VERSION 5.7 ;
BUSBITCHARS "[]" ;
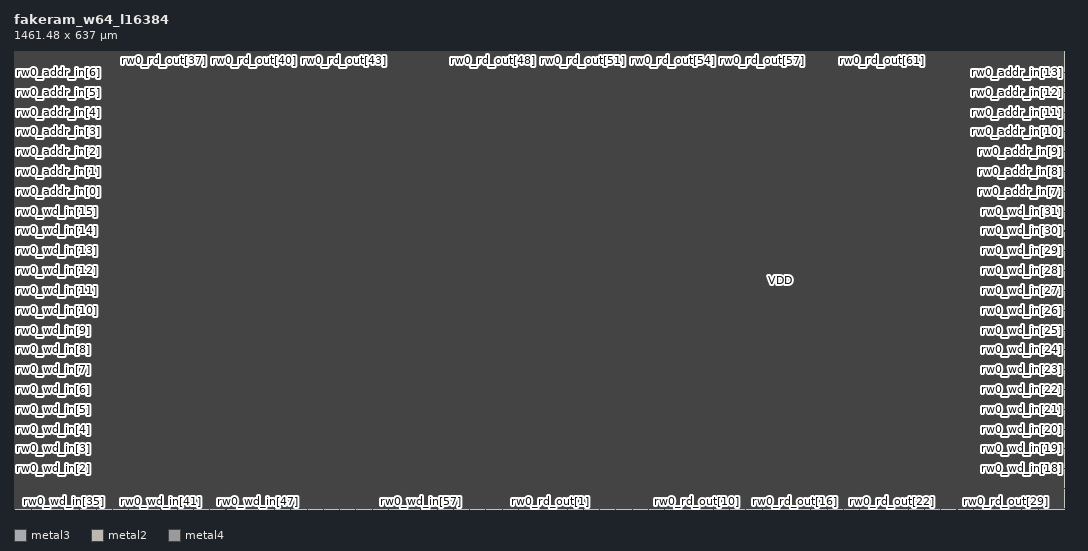
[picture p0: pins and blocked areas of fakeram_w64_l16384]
MACRO fakeram_w64_l16384
  FOREIGN fakeram_w64_l16384 0 0 ;
  SYMMETRY X Y R90 ;
  SIZE 1461.480 BY 637.000 ;
  CLASS BLOCK ;
  PIN rw0_wd_in[0]
    DIRECTION INPUT ;
    USE SIGNAL ;
    SHAPE ABUTMENT ;
    PORT
      LAYER metal3 ;
      RECT 0.000 0.805 0.210 0.875 ;
    END
  END rw0_wd_in[0]
  PIN rw0_wd_in[1]
    DIRECTION INPUT ;
    USE SIGNAL ;
    SHAPE ABUTMENT ;
    PORT
      LAYER metal3 ;
      RECT 0.000 28.385 0.210 28.455 ;
    END
  END rw0_wd_in[1]
  PIN rw0_wd_in[2]
    DIRECTION INPUT ;
    USE SIGNAL ;
    SHAPE ABUTMENT ;
    PORT
      LAYER metal3 ;
      RECT 0.000 55.965 0.210 56.035 ;
    END
  END rw0_wd_in[2]
  PIN rw0_wd_in[3]
    DIRECTION INPUT ;
    USE SIGNAL ;
    SHAPE ABUTMENT ;
    PORT
      LAYER metal3 ;
      RECT 0.000 83.545 0.210 83.615 ;
    END
  END rw0_wd_in[3]
  PIN rw0_wd_in[4]
    DIRECTION INPUT ;
    USE SIGNAL ;
    SHAPE ABUTMENT ;
    PORT
      LAYER metal3 ;
      RECT 0.000 111.125 0.210 111.195 ;
    END
  END rw0_wd_in[4]
  PIN rw0_wd_in[5]
    DIRECTION INPUT ;
    USE SIGNAL ;
    SHAPE ABUTMENT ;
    PORT
      LAYER metal3 ;
      RECT 0.000 138.705 0.210 138.775 ;
    END
  END rw0_wd_in[5]
  PIN rw0_wd_in[6]
    DIRECTION INPUT ;
    USE SIGNAL ;
    SHAPE ABUTMENT ;
    PORT
      LAYER metal3 ;
      RECT 0.000 166.285 0.210 166.355 ;
    END
  END rw0_wd_in[6]
  PIN rw0_wd_in[7]
    DIRECTION INPUT ;
    USE SIGNAL ;
    SHAPE ABUTMENT ;
    PORT
      LAYER metal3 ;
      RECT 0.000 193.865 0.210 193.935 ;
    END
  END rw0_wd_in[7]
  PIN rw0_wd_in[8]
    DIRECTION INPUT ;
    USE SIGNAL ;
    SHAPE ABUTMENT ;
    PORT
      LAYER metal3 ;
      RECT 0.000 221.445 0.210 221.515 ;
    END
  END rw0_wd_in[8]
  PIN rw0_wd_in[9]
    DIRECTION INPUT ;
    USE SIGNAL ;
    SHAPE ABUTMENT ;
    PORT
      LAYER metal3 ;
      RECT 0.000 249.025 0.210 249.095 ;
    END
  END rw0_wd_in[9]
  PIN rw0_wd_in[10]
    DIRECTION INPUT ;
    USE SIGNAL ;
    SHAPE ABUTMENT ;
    PORT
      LAYER metal3 ;
      RECT 0.000 276.605 0.210 276.675 ;
    END
  END rw0_wd_in[10]
  PIN rw0_wd_in[11]
    DIRECTION INPUT ;
    USE SIGNAL ;
    SHAPE ABUTMENT ;
    PORT
      LAYER metal3 ;
      RECT 0.000 304.185 0.210 304.255 ;
    END
  END rw0_wd_in[11]
  PIN rw0_wd_in[12]
    DIRECTION INPUT ;
    USE SIGNAL ;
    SHAPE ABUTMENT ;
    PORT
      LAYER metal3 ;
      RECT 0.000 331.765 0.210 331.835 ;
    END
  END rw0_wd_in[12]
  PIN rw0_wd_in[13]
    DIRECTION INPUT ;
    USE SIGNAL ;
    SHAPE ABUTMENT ;
    PORT
      LAYER metal3 ;
      RECT 0.000 359.345 0.210 359.415 ;
    END
  END rw0_wd_in[13]
  PIN rw0_wd_in[14]
    DIRECTION INPUT ;
    USE SIGNAL ;
    SHAPE ABUTMENT ;
    PORT
      LAYER metal3 ;
      RECT 0.000 386.925 0.210 386.995 ;
    END
  END rw0_wd_in[14]
  PIN rw0_wd_in[15]
    DIRECTION INPUT ;
    USE SIGNAL ;
    SHAPE ABUTMENT ;
    PORT
      LAYER metal3 ;
      RECT 0.000 414.505 0.210 414.575 ;
    END
  END rw0_wd_in[15]
  PIN rw0_wd_in[16]
    DIRECTION INPUT ;
    USE SIGNAL ;
    SHAPE ABUTMENT ;
    PORT
      LAYER metal3 ;
      RECT 1461.270 0.805 1461.480 0.875 ;
    END
  END rw0_wd_in[16]
  PIN rw0_wd_in[17]
    DIRECTION INPUT ;
    USE SIGNAL ;
    SHAPE ABUTMENT ;
    PORT
      LAYER metal3 ;
      RECT 1461.270 28.385 1461.480 28.455 ;
    END
  END rw0_wd_in[17]
  PIN rw0_wd_in[18]
    DIRECTION INPUT ;
    USE SIGNAL ;
    SHAPE ABUTMENT ;
    PORT
      LAYER metal3 ;
      RECT 1461.270 55.965 1461.480 56.035 ;
    END
  END rw0_wd_in[18]
  PIN rw0_wd_in[19]
    DIRECTION INPUT ;
    USE SIGNAL ;
    SHAPE ABUTMENT ;
    PORT
      LAYER metal3 ;
      RECT 1461.270 83.545 1461.480 83.615 ;
    END
  END rw0_wd_in[19]
  PIN rw0_wd_in[20]
    DIRECTION INPUT ;
    USE SIGNAL ;
    SHAPE ABUTMENT ;
    PORT
      LAYER metal3 ;
      RECT 1461.270 111.125 1461.480 111.195 ;
    END
  END rw0_wd_in[20]
  PIN rw0_wd_in[21]
    DIRECTION INPUT ;
    USE SIGNAL ;
    SHAPE ABUTMENT ;
    PORT
      LAYER metal3 ;
      RECT 1461.270 138.705 1461.480 138.775 ;
    END
  END rw0_wd_in[21]
  PIN rw0_wd_in[22]
    DIRECTION INPUT ;
    USE SIGNAL ;
    SHAPE ABUTMENT ;
    PORT
      LAYER metal3 ;
      RECT 1461.270 166.285 1461.480 166.355 ;
    END
  END rw0_wd_in[22]
  PIN rw0_wd_in[23]
    DIRECTION INPUT ;
    USE SIGNAL ;
    SHAPE ABUTMENT ;
    PORT
      LAYER metal3 ;
      RECT 1461.270 193.865 1461.480 193.935 ;
    END
  END rw0_wd_in[23]
  PIN rw0_wd_in[24]
    DIRECTION INPUT ;
    USE SIGNAL ;
    SHAPE ABUTMENT ;
    PORT
      LAYER metal3 ;
      RECT 1461.270 221.445 1461.480 221.515 ;
    END
  END rw0_wd_in[24]
  PIN rw0_wd_in[25]
    DIRECTION INPUT ;
    USE SIGNAL ;
    SHAPE ABUTMENT ;
    PORT
      LAYER metal3 ;
      RECT 1461.270 249.025 1461.480 249.095 ;
    END
  END rw0_wd_in[25]
  PIN rw0_wd_in[26]
    DIRECTION INPUT ;
    USE SIGNAL ;
    SHAPE ABUTMENT ;
    PORT
      LAYER metal3 ;
      RECT 1461.270 276.605 1461.480 276.675 ;
    END
  END rw0_wd_in[26]
  PIN rw0_wd_in[27]
    DIRECTION INPUT ;
    USE SIGNAL ;
    SHAPE ABUTMENT ;
    PORT
      LAYER metal3 ;
      RECT 1461.270 304.185 1461.480 304.255 ;
    END
  END rw0_wd_in[27]
  PIN rw0_wd_in[28]
    DIRECTION INPUT ;
    USE SIGNAL ;
    SHAPE ABUTMENT ;
    PORT
      LAYER metal3 ;
      RECT 1461.270 331.765 1461.480 331.835 ;
    END
  END rw0_wd_in[28]
  PIN rw0_wd_in[29]
    DIRECTION INPUT ;
    USE SIGNAL ;
    SHAPE ABUTMENT ;
    PORT
      LAYER metal3 ;
      RECT 1461.270 359.345 1461.480 359.415 ;
    END
  END rw0_wd_in[29]
  PIN rw0_wd_in[30]
    DIRECTION INPUT ;
    USE SIGNAL ;
    SHAPE ABUTMENT ;
    PORT
      LAYER metal3 ;
      RECT 1461.270 386.925 1461.480 386.995 ;
    END
  END rw0_wd_in[30]
  PIN rw0_wd_in[31]
    DIRECTION INPUT ;
    USE SIGNAL ;
    SHAPE ABUTMENT ;
    PORT
      LAYER metal3 ;
      RECT 1461.270 414.505 1461.480 414.575 ;
    END
  END rw0_wd_in[31]
  PIN rw0_wd_in[32]
    DIRECTION INPUT ;
    USE SIGNAL ;
    SHAPE ABUTMENT ;
    PORT
      LAYER metal2 ;
      RECT 1.105 0.000 1.175 0.210 ;
    END
  END rw0_wd_in[32]
  PIN rw0_wd_in[33]
    DIRECTION INPUT ;
    USE SIGNAL ;
    SHAPE ABUTMENT ;
    PORT
      LAYER metal2 ;
      RECT 23.715 0.000 23.785 0.210 ;
    END
  END rw0_wd_in[33]
  PIN rw0_wd_in[34]
    DIRECTION INPUT ;
    USE SIGNAL ;
    SHAPE ABUTMENT ;
    PORT
      LAYER metal2 ;
      RECT 46.325 0.000 46.395 0.210 ;
    END
  END rw0_wd_in[34]
  PIN rw0_wd_in[35]
    DIRECTION INPUT ;
    USE SIGNAL ;
    SHAPE ABUTMENT ;
    PORT
      LAYER metal2 ;
      RECT 68.935 0.000 69.005 0.210 ;
    END
  END rw0_wd_in[35]
  PIN rw0_wd_in[36]
    DIRECTION INPUT ;
    USE SIGNAL ;
    SHAPE ABUTMENT ;
    PORT
      LAYER metal2 ;
      RECT 91.545 0.000 91.615 0.210 ;
    END
  END rw0_wd_in[36]
  PIN rw0_wd_in[37]
    DIRECTION INPUT ;
    USE SIGNAL ;
    SHAPE ABUTMENT ;
    PORT
      LAYER metal2 ;
      RECT 114.155 0.000 114.225 0.210 ;
    END
  END rw0_wd_in[37]
  PIN rw0_wd_in[38]
    DIRECTION INPUT ;
    USE SIGNAL ;
    SHAPE ABUTMENT ;
    PORT
      LAYER metal2 ;
      RECT 136.765 0.000 136.835 0.210 ;
    END
  END rw0_wd_in[38]
  PIN rw0_wd_in[39]
    DIRECTION INPUT ;
    USE SIGNAL ;
    SHAPE ABUTMENT ;
    PORT
      LAYER metal2 ;
      RECT 159.375 0.000 159.445 0.210 ;
    END
  END rw0_wd_in[39]
  PIN rw0_wd_in[40]
    DIRECTION INPUT ;
    USE SIGNAL ;
    SHAPE ABUTMENT ;
    PORT
      LAYER metal2 ;
      RECT 181.985 0.000 182.055 0.210 ;
    END
  END rw0_wd_in[40]
  PIN rw0_wd_in[41]
    DIRECTION INPUT ;
    USE SIGNAL ;
    SHAPE ABUTMENT ;
    PORT
      LAYER metal2 ;
      RECT 204.595 0.000 204.665 0.210 ;
    END
  END rw0_wd_in[41]
  PIN rw0_wd_in[42]
    DIRECTION INPUT ;
    USE SIGNAL ;
    SHAPE ABUTMENT ;
    PORT
      LAYER metal2 ;
      RECT 227.205 0.000 227.275 0.210 ;
    END
  END rw0_wd_in[42]
  PIN rw0_wd_in[43]
    DIRECTION INPUT ;
    USE SIGNAL ;
    SHAPE ABUTMENT ;
    PORT
      LAYER metal2 ;
      RECT 249.815 0.000 249.885 0.210 ;
    END
  END rw0_wd_in[43]
  PIN rw0_wd_in[44]
    DIRECTION INPUT ;
    USE SIGNAL ;
    SHAPE ABUTMENT ;
    PORT
      LAYER metal2 ;
      RECT 272.425 0.000 272.495 0.210 ;
    END
  END rw0_wd_in[44]
  PIN rw0_wd_in[45]
    DIRECTION INPUT ;
    USE SIGNAL ;
    SHAPE ABUTMENT ;
    PORT
      LAYER metal2 ;
      RECT 295.035 0.000 295.105 0.210 ;
    END
  END rw0_wd_in[45]
  PIN rw0_wd_in[46]
    DIRECTION INPUT ;
    USE SIGNAL ;
    SHAPE ABUTMENT ;
    PORT
      LAYER metal2 ;
      RECT 317.645 0.000 317.715 0.210 ;
    END
  END rw0_wd_in[46]
  PIN rw0_wd_in[47]
    DIRECTION INPUT ;
    USE SIGNAL ;
    SHAPE ABUTMENT ;
    PORT
      LAYER metal2 ;
      RECT 340.255 0.000 340.325 0.210 ;
    END
  END rw0_wd_in[47]
  PIN rw0_wd_in[48]
    DIRECTION INPUT ;
    USE SIGNAL ;
    SHAPE ABUTMENT ;
    PORT
      LAYER metal2 ;
      RECT 362.865 0.000 362.935 0.210 ;
    END
  END rw0_wd_in[48]
  PIN rw0_wd_in[49]
    DIRECTION INPUT ;
    USE SIGNAL ;
    SHAPE ABUTMENT ;
    PORT
      LAYER metal2 ;
      RECT 385.475 0.000 385.545 0.210 ;
    END
  END rw0_wd_in[49]
  PIN rw0_wd_in[50]
    DIRECTION INPUT ;
    USE SIGNAL ;
    SHAPE ABUTMENT ;
    PORT
      LAYER metal2 ;
      RECT 408.085 0.000 408.155 0.210 ;
    END
  END rw0_wd_in[50]
  PIN rw0_wd_in[51]
    DIRECTION INPUT ;
    USE SIGNAL ;
    SHAPE ABUTMENT ;
    PORT
      LAYER metal2 ;
      RECT 430.695 0.000 430.765 0.210 ;
    END
  END rw0_wd_in[51]
  PIN rw0_wd_in[52]
    DIRECTION INPUT ;
    USE SIGNAL ;
    SHAPE ABUTMENT ;
    PORT
      LAYER metal2 ;
      RECT 453.305 0.000 453.375 0.210 ;
    END
  END rw0_wd_in[52]
  PIN rw0_wd_in[53]
    DIRECTION INPUT ;
    USE SIGNAL ;
    SHAPE ABUTMENT ;
    PORT
      LAYER metal2 ;
      RECT 475.915 0.000 475.985 0.210 ;
    END
  END rw0_wd_in[53]
  PIN rw0_wd_in[54]
    DIRECTION INPUT ;
    USE SIGNAL ;
    SHAPE ABUTMENT ;
    PORT
      LAYER metal2 ;
      RECT 498.525 0.000 498.595 0.210 ;
    END
  END rw0_wd_in[54]
  PIN rw0_wd_in[55]
    DIRECTION INPUT ;
    USE SIGNAL ;
    SHAPE ABUTMENT ;
    PORT
      LAYER metal2 ;
      RECT 521.135 0.000 521.205 0.210 ;
    END
  END rw0_wd_in[55]
  PIN rw0_wd_in[56]
    DIRECTION INPUT ;
    USE SIGNAL ;
    SHAPE ABUTMENT ;
    PORT
      LAYER metal2 ;
      RECT 543.745 0.000 543.815 0.210 ;
    END
  END rw0_wd_in[56]
  PIN rw0_wd_in[57]
    DIRECTION INPUT ;
    USE SIGNAL ;
    SHAPE ABUTMENT ;
    PORT
      LAYER metal2 ;
      RECT 566.355 0.000 566.425 0.210 ;
    END
  END rw0_wd_in[57]
  PIN rw0_wd_in[58]
    DIRECTION INPUT ;
    USE SIGNAL ;
    SHAPE ABUTMENT ;
    PORT
      LAYER metal2 ;
      RECT 588.965 0.000 589.035 0.210 ;
    END
  END rw0_wd_in[58]
  PIN rw0_wd_in[59]
    DIRECTION INPUT ;
    USE SIGNAL ;
    SHAPE ABUTMENT ;
    PORT
      LAYER metal2 ;
      RECT 611.575 0.000 611.645 0.210 ;
    END
  END rw0_wd_in[59]
  PIN rw0_wd_in[60]
    DIRECTION INPUT ;
    USE SIGNAL ;
    SHAPE ABUTMENT ;
    PORT
      LAYER metal2 ;
      RECT 634.185 0.000 634.255 0.210 ;
    END
  END rw0_wd_in[60]
  PIN rw0_wd_in[61]
    DIRECTION INPUT ;
    USE SIGNAL ;
    SHAPE ABUTMENT ;
    PORT
      LAYER metal2 ;
      RECT 656.795 0.000 656.865 0.210 ;
    END
  END rw0_wd_in[61]
  PIN rw0_wd_in[62]
    DIRECTION INPUT ;
    USE SIGNAL ;
    SHAPE ABUTMENT ;
    PORT
      LAYER metal2 ;
      RECT 679.405 0.000 679.475 0.210 ;
    END
  END rw0_wd_in[62]
  PIN rw0_wd_in[63]
    DIRECTION INPUT ;
    USE SIGNAL ;
    SHAPE ABUTMENT ;
    PORT
      LAYER metal2 ;
      RECT 702.015 0.000 702.085 0.210 ;
    END
  END rw0_wd_in[63]
  PIN rw0_rd_out[0]
    DIRECTION OUTPUT ;
    USE SIGNAL ;
    SHAPE ABUTMENT ;
    PORT
      LAYER metal2 ;
      RECT 724.625 0.000 724.695 0.210 ;
    END
  END rw0_rd_out[0]
  PIN rw0_rd_out[1]
    DIRECTION OUTPUT ;
    USE SIGNAL ;
    SHAPE ABUTMENT ;
    PORT
      LAYER metal2 ;
      RECT 747.235 0.000 747.305 0.210 ;
    END
  END rw0_rd_out[1]
  PIN rw0_rd_out[2]
    DIRECTION OUTPUT ;
    USE SIGNAL ;
    SHAPE ABUTMENT ;
    PORT
      LAYER metal2 ;
      RECT 769.845 0.000 769.915 0.210 ;
    END
  END rw0_rd_out[2]
  PIN rw0_rd_out[3]
    DIRECTION OUTPUT ;
    USE SIGNAL ;
    SHAPE ABUTMENT ;
    PORT
      LAYER metal2 ;
      RECT 792.455 0.000 792.525 0.210 ;
    END
  END rw0_rd_out[3]
  PIN rw0_rd_out[4]
    DIRECTION OUTPUT ;
    USE SIGNAL ;
    SHAPE ABUTMENT ;
    PORT
      LAYER metal2 ;
      RECT 815.065 0.000 815.135 0.210 ;
    END
  END rw0_rd_out[4]
  PIN rw0_rd_out[5]
    DIRECTION OUTPUT ;
    USE SIGNAL ;
    SHAPE ABUTMENT ;
    PORT
      LAYER metal2 ;
      RECT 837.675 0.000 837.745 0.210 ;
    END
  END rw0_rd_out[5]
  PIN rw0_rd_out[6]
    DIRECTION OUTPUT ;
    USE SIGNAL ;
    SHAPE ABUTMENT ;
    PORT
      LAYER metal2 ;
      RECT 860.285 0.000 860.355 0.210 ;
    END
  END rw0_rd_out[6]
  PIN rw0_rd_out[7]
    DIRECTION OUTPUT ;
    USE SIGNAL ;
    SHAPE ABUTMENT ;
    PORT
      LAYER metal2 ;
      RECT 882.895 0.000 882.965 0.210 ;
    END
  END rw0_rd_out[7]
  PIN rw0_rd_out[8]
    DIRECTION OUTPUT ;
    USE SIGNAL ;
    SHAPE ABUTMENT ;
    PORT
      LAYER metal2 ;
      RECT 905.505 0.000 905.575 0.210 ;
    END
  END rw0_rd_out[8]
  PIN rw0_rd_out[9]
    DIRECTION OUTPUT ;
    USE SIGNAL ;
    SHAPE ABUTMENT ;
    PORT
      LAYER metal2 ;
      RECT 928.115 0.000 928.185 0.210 ;
    END
  END rw0_rd_out[9]
  PIN rw0_rd_out[10]
    DIRECTION OUTPUT ;
    USE SIGNAL ;
    SHAPE ABUTMENT ;
    PORT
      LAYER metal2 ;
      RECT 950.725 0.000 950.795 0.210 ;
    END
  END rw0_rd_out[10]
  PIN rw0_rd_out[11]
    DIRECTION OUTPUT ;
    USE SIGNAL ;
    SHAPE ABUTMENT ;
    PORT
      LAYER metal2 ;
      RECT 973.335 0.000 973.405 0.210 ;
    END
  END rw0_rd_out[11]
  PIN rw0_rd_out[12]
    DIRECTION OUTPUT ;
    USE SIGNAL ;
    SHAPE ABUTMENT ;
    PORT
      LAYER metal2 ;
      RECT 995.945 0.000 996.015 0.210 ;
    END
  END rw0_rd_out[12]
  PIN rw0_rd_out[13]
    DIRECTION OUTPUT ;
    USE SIGNAL ;
    SHAPE ABUTMENT ;
    PORT
      LAYER metal2 ;
      RECT 1018.555 0.000 1018.625 0.210 ;
    END
  END rw0_rd_out[13]
  PIN rw0_rd_out[14]
    DIRECTION OUTPUT ;
    USE SIGNAL ;
    SHAPE ABUTMENT ;
    PORT
      LAYER metal2 ;
      RECT 1041.165 0.000 1041.235 0.210 ;
    END
  END rw0_rd_out[14]
  PIN rw0_rd_out[15]
    DIRECTION OUTPUT ;
    USE SIGNAL ;
    SHAPE ABUTMENT ;
    PORT
      LAYER metal2 ;
      RECT 1063.775 0.000 1063.845 0.210 ;
    END
  END rw0_rd_out[15]
  PIN rw0_rd_out[16]
    DIRECTION OUTPUT ;
    USE SIGNAL ;
    SHAPE ABUTMENT ;
    PORT
      LAYER metal2 ;
      RECT 1086.385 0.000 1086.455 0.210 ;
    END
  END rw0_rd_out[16]
  PIN rw0_rd_out[17]
    DIRECTION OUTPUT ;
    USE SIGNAL ;
    SHAPE ABUTMENT ;
    PORT
      LAYER metal2 ;
      RECT 1108.995 0.000 1109.065 0.210 ;
    END
  END rw0_rd_out[17]
  PIN rw0_rd_out[18]
    DIRECTION OUTPUT ;
    USE SIGNAL ;
    SHAPE ABUTMENT ;
    PORT
      LAYER metal2 ;
      RECT 1131.605 0.000 1131.675 0.210 ;
    END
  END rw0_rd_out[18]
  PIN rw0_rd_out[19]
    DIRECTION OUTPUT ;
    USE SIGNAL ;
    SHAPE ABUTMENT ;
    PORT
      LAYER metal2 ;
      RECT 1154.215 0.000 1154.285 0.210 ;
    END
  END rw0_rd_out[19]
  PIN rw0_rd_out[20]
    DIRECTION OUTPUT ;
    USE SIGNAL ;
    SHAPE ABUTMENT ;
    PORT
      LAYER metal2 ;
      RECT 1176.825 0.000 1176.895 0.210 ;
    END
  END rw0_rd_out[20]
  PIN rw0_rd_out[21]
    DIRECTION OUTPUT ;
    USE SIGNAL ;
    SHAPE ABUTMENT ;
    PORT
      LAYER metal2 ;
      RECT 1199.435 0.000 1199.505 0.210 ;
    END
  END rw0_rd_out[21]
  PIN rw0_rd_out[22]
    DIRECTION OUTPUT ;
    USE SIGNAL ;
    SHAPE ABUTMENT ;
    PORT
      LAYER metal2 ;
      RECT 1222.045 0.000 1222.115 0.210 ;
    END
  END rw0_rd_out[22]
  PIN rw0_rd_out[23]
    DIRECTION OUTPUT ;
    USE SIGNAL ;
    SHAPE ABUTMENT ;
    PORT
      LAYER metal2 ;
      RECT 1244.655 0.000 1244.725 0.210 ;
    END
  END rw0_rd_out[23]
  PIN rw0_rd_out[24]
    DIRECTION OUTPUT ;
    USE SIGNAL ;
    SHAPE ABUTMENT ;
    PORT
      LAYER metal2 ;
      RECT 1267.265 0.000 1267.335 0.210 ;
    END
  END rw0_rd_out[24]
  PIN rw0_rd_out[25]
    DIRECTION OUTPUT ;
    USE SIGNAL ;
    SHAPE ABUTMENT ;
    PORT
      LAYER metal2 ;
      RECT 1289.875 0.000 1289.945 0.210 ;
    END
  END rw0_rd_out[25]
  PIN rw0_rd_out[26]
    DIRECTION OUTPUT ;
    USE SIGNAL ;
    SHAPE ABUTMENT ;
    PORT
      LAYER metal2 ;
      RECT 1312.485 0.000 1312.555 0.210 ;
    END
  END rw0_rd_out[26]
  PIN rw0_rd_out[27]
    DIRECTION OUTPUT ;
    USE SIGNAL ;
    SHAPE ABUTMENT ;
    PORT
      LAYER metal2 ;
      RECT 1335.095 0.000 1335.165 0.210 ;
    END
  END rw0_rd_out[27]
  PIN rw0_rd_out[28]
    DIRECTION OUTPUT ;
    USE SIGNAL ;
    SHAPE ABUTMENT ;
    PORT
      LAYER metal2 ;
      RECT 1357.705 0.000 1357.775 0.210 ;
    END
  END rw0_rd_out[28]
  PIN rw0_rd_out[29]
    DIRECTION OUTPUT ;
    USE SIGNAL ;
    SHAPE ABUTMENT ;
    PORT
      LAYER metal2 ;
      RECT 1380.315 0.000 1380.385 0.210 ;
    END
  END rw0_rd_out[29]
  PIN rw0_rd_out[30]
    DIRECTION OUTPUT ;
    USE SIGNAL ;
    SHAPE ABUTMENT ;
    PORT
      LAYER metal2 ;
      RECT 1402.925 0.000 1402.995 0.210 ;
    END
  END rw0_rd_out[30]
  PIN rw0_rd_out[31]
    DIRECTION OUTPUT ;
    USE SIGNAL ;
    SHAPE ABUTMENT ;
    PORT
      LAYER metal2 ;
      RECT 1425.535 0.000 1425.605 0.210 ;
    END
  END rw0_rd_out[31]
  PIN rw0_rd_out[32]
    DIRECTION OUTPUT ;
    USE SIGNAL ;
    SHAPE ABUTMENT ;
    PORT
      LAYER metal2 ;
      RECT 1.105 636.790 1.175 637.000 ;
    END
  END rw0_rd_out[32]
  PIN rw0_rd_out[33]
    DIRECTION OUTPUT ;
    USE SIGNAL ;
    SHAPE ABUTMENT ;
    PORT
      LAYER metal2 ;
      RECT 42.715 636.790 42.785 637.000 ;
    END
  END rw0_rd_out[33]
  PIN rw0_rd_out[34]
    DIRECTION OUTPUT ;
    USE SIGNAL ;
    SHAPE ABUTMENT ;
    PORT
      LAYER metal2 ;
      RECT 84.325 636.790 84.395 637.000 ;
    END
  END rw0_rd_out[34]
  PIN rw0_rd_out[35]
    DIRECTION OUTPUT ;
    USE SIGNAL ;
    SHAPE ABUTMENT ;
    PORT
      LAYER metal2 ;
      RECT 125.935 636.790 126.005 637.000 ;
    END
  END rw0_rd_out[35]
  PIN rw0_rd_out[36]
    DIRECTION OUTPUT ;
    USE SIGNAL ;
    SHAPE ABUTMENT ;
    PORT
      LAYER metal2 ;
      RECT 167.545 636.790 167.615 637.000 ;
    END
  END rw0_rd_out[36]
  PIN rw0_rd_out[37]
    DIRECTION OUTPUT ;
    USE SIGNAL ;
    SHAPE ABUTMENT ;
    PORT
      LAYER metal2 ;
      RECT 209.155 636.790 209.225 637.000 ;
    END
  END rw0_rd_out[37]
  PIN rw0_rd_out[38]
    DIRECTION OUTPUT ;
    USE SIGNAL ;
    SHAPE ABUTMENT ;
    PORT
      LAYER metal2 ;
      RECT 250.765 636.790 250.835 637.000 ;
    END
  END rw0_rd_out[38]
  PIN rw0_rd_out[39]
    DIRECTION OUTPUT ;
    USE SIGNAL ;
    SHAPE ABUTMENT ;
    PORT
      LAYER metal2 ;
      RECT 292.375 636.790 292.445 637.000 ;
    END
  END rw0_rd_out[39]
  PIN rw0_rd_out[40]
    DIRECTION OUTPUT ;
    USE SIGNAL ;
    SHAPE ABUTMENT ;
    PORT
      LAYER metal2 ;
      RECT 333.985 636.790 334.055 637.000 ;
    END
  END rw0_rd_out[40]
  PIN rw0_rd_out[41]
    DIRECTION OUTPUT ;
    USE SIGNAL ;
    SHAPE ABUTMENT ;
    PORT
      LAYER metal2 ;
      RECT 375.595 636.790 375.665 637.000 ;
    END
  END rw0_rd_out[41]
  PIN rw0_rd_out[42]
    DIRECTION OUTPUT ;
    USE SIGNAL ;
    SHAPE ABUTMENT ;
    PORT
      LAYER metal2 ;
      RECT 417.205 636.790 417.275 637.000 ;
    END
  END rw0_rd_out[42]
  PIN rw0_rd_out[43]
    DIRECTION OUTPUT ;
    USE SIGNAL ;
    SHAPE ABUTMENT ;
    PORT
      LAYER metal2 ;
      RECT 458.815 636.790 458.885 637.000 ;
    END
  END rw0_rd_out[43]
  PIN rw0_rd_out[44]
    DIRECTION OUTPUT ;
    USE SIGNAL ;
    SHAPE ABUTMENT ;
    PORT
      LAYER metal2 ;
      RECT 500.425 636.790 500.495 637.000 ;
    END
  END rw0_rd_out[44]
  PIN rw0_rd_out[45]
    DIRECTION OUTPUT ;
    USE SIGNAL ;
    SHAPE ABUTMENT ;
    PORT
      LAYER metal2 ;
      RECT 542.035 636.790 542.105 637.000 ;
    END
  END rw0_rd_out[45]
  PIN rw0_rd_out[46]
    DIRECTION OUTPUT ;
    USE SIGNAL ;
    SHAPE ABUTMENT ;
    PORT
      LAYER metal2 ;
      RECT 583.645 636.790 583.715 637.000 ;
    END
  END rw0_rd_out[46]
  PIN rw0_rd_out[47]
    DIRECTION OUTPUT ;
    USE SIGNAL ;
    SHAPE ABUTMENT ;
    PORT
      LAYER metal2 ;
      RECT 625.255 636.790 625.325 637.000 ;
    END
  END rw0_rd_out[47]
  PIN rw0_rd_out[48]
    DIRECTION OUTPUT ;
    USE SIGNAL ;
    SHAPE ABUTMENT ;
    PORT
      LAYER metal2 ;
      RECT 666.865 636.790 666.935 637.000 ;
    END
  END rw0_rd_out[48]
  PIN rw0_rd_out[49]
    DIRECTION OUTPUT ;
    USE SIGNAL ;
    SHAPE ABUTMENT ;
    PORT
      LAYER metal2 ;
      RECT 708.475 636.790 708.545 637.000 ;
    END
  END rw0_rd_out[49]
  PIN rw0_rd_out[50]
    DIRECTION OUTPUT ;
    USE SIGNAL ;
    SHAPE ABUTMENT ;
    PORT
      LAYER metal2 ;
      RECT 750.085 636.790 750.155 637.000 ;
    END
  END rw0_rd_out[50]
  PIN rw0_rd_out[51]
    DIRECTION OUTPUT ;
    USE SIGNAL ;
    SHAPE ABUTMENT ;
    PORT
      LAYER metal2 ;
      RECT 791.695 636.790 791.765 637.000 ;
    END
  END rw0_rd_out[51]
  PIN rw0_rd_out[52]
    DIRECTION OUTPUT ;
    USE SIGNAL ;
    SHAPE ABUTMENT ;
    PORT
      LAYER metal2 ;
      RECT 833.305 636.790 833.375 637.000 ;
    END
  END rw0_rd_out[52]
  PIN rw0_rd_out[53]
    DIRECTION OUTPUT ;
    USE SIGNAL ;
    SHAPE ABUTMENT ;
    PORT
      LAYER metal2 ;
      RECT 874.915 636.790 874.985 637.000 ;
    END
  END rw0_rd_out[53]
  PIN rw0_rd_out[54]
    DIRECTION OUTPUT ;
    USE SIGNAL ;
    SHAPE ABUTMENT ;
    PORT
      LAYER metal2 ;
      RECT 916.525 636.790 916.595 637.000 ;
    END
  END rw0_rd_out[54]
  PIN rw0_rd_out[55]
    DIRECTION OUTPUT ;
    USE SIGNAL ;
    SHAPE ABUTMENT ;
    PORT
      LAYER metal2 ;
      RECT 958.135 636.790 958.205 637.000 ;
    END
  END rw0_rd_out[55]
  PIN rw0_rd_out[56]
    DIRECTION OUTPUT ;
    USE SIGNAL ;
    SHAPE ABUTMENT ;
    PORT
      LAYER metal2 ;
      RECT 999.745 636.790 999.815 637.000 ;
    END
  END rw0_rd_out[56]
  PIN rw0_rd_out[57]
    DIRECTION OUTPUT ;
    USE SIGNAL ;
    SHAPE ABUTMENT ;
    PORT
      LAYER metal2 ;
      RECT 1041.355 636.790 1041.425 637.000 ;
    END
  END rw0_rd_out[57]
  PIN rw0_rd_out[58]
    DIRECTION OUTPUT ;
    USE SIGNAL ;
    SHAPE ABUTMENT ;
    PORT
      LAYER metal2 ;
      RECT 1082.965 636.790 1083.035 637.000 ;
    END
  END rw0_rd_out[58]
  PIN rw0_rd_out[59]
    DIRECTION OUTPUT ;
    USE SIGNAL ;
    SHAPE ABUTMENT ;
    PORT
      LAYER metal2 ;
      RECT 1124.575 636.790 1124.645 637.000 ;
    END
  END rw0_rd_out[59]
  PIN rw0_rd_out[60]
    DIRECTION OUTPUT ;
    USE SIGNAL ;
    SHAPE ABUTMENT ;
    PORT
      LAYER metal2 ;
      RECT 1166.185 636.790 1166.255 637.000 ;
    END
  END rw0_rd_out[60]
  PIN rw0_rd_out[61]
    DIRECTION OUTPUT ;
    USE SIGNAL ;
    SHAPE ABUTMENT ;
    PORT
      LAYER metal2 ;
      RECT 1207.795 636.790 1207.865 637.000 ;
    END
  END rw0_rd_out[61]
  PIN rw0_rd_out[62]
    DIRECTION OUTPUT ;
    USE SIGNAL ;
    SHAPE ABUTMENT ;
    PORT
      LAYER metal2 ;
      RECT 1249.405 636.790 1249.475 637.000 ;
    END
  END rw0_rd_out[62]
  PIN rw0_rd_out[63]
    DIRECTION OUTPUT ;
    USE SIGNAL ;
    SHAPE ABUTMENT ;
    PORT
      LAYER metal2 ;
      RECT 1291.015 636.790 1291.085 637.000 ;
    END
  END rw0_rd_out[63]
  PIN rw0_addr_in[0]
    DIRECTION INPUT ;
    USE SIGNAL ;
    SHAPE ABUTMENT ;
    PORT
      LAYER metal3 ;
      RECT 0.000 442.085 0.210 442.155 ;
    END
  END rw0_addr_in[0]
  PIN rw0_addr_in[1]
    DIRECTION INPUT ;
    USE SIGNAL ;
    SHAPE ABUTMENT ;
    PORT
      LAYER metal3 ;
      RECT 0.000 469.665 0.210 469.735 ;
    END
  END rw0_addr_in[1]
  PIN rw0_addr_in[2]
    DIRECTION INPUT ;
    USE SIGNAL ;
    SHAPE ABUTMENT ;
    PORT
      LAYER metal3 ;
      RECT 0.000 497.245 0.210 497.315 ;
    END
  END rw0_addr_in[2]
  PIN rw0_addr_in[3]
    DIRECTION INPUT ;
    USE SIGNAL ;
    SHAPE ABUTMENT ;
    PORT
      LAYER metal3 ;
      RECT 0.000 524.825 0.210 524.895 ;
    END
  END rw0_addr_in[3]
  PIN rw0_addr_in[4]
    DIRECTION INPUT ;
    USE SIGNAL ;
    SHAPE ABUTMENT ;
    PORT
      LAYER metal3 ;
      RECT 0.000 552.405 0.210 552.475 ;
    END
  END rw0_addr_in[4]
  PIN rw0_addr_in[5]
    DIRECTION INPUT ;
    USE SIGNAL ;
    SHAPE ABUTMENT ;
    PORT
      LAYER metal3 ;
      RECT 0.000 579.985 0.210 580.055 ;
    END
  END rw0_addr_in[5]
  PIN rw0_addr_in[6]
    DIRECTION INPUT ;
    USE SIGNAL ;
    SHAPE ABUTMENT ;
    PORT
      LAYER metal3 ;
      RECT 0.000 607.565 0.210 607.635 ;
    END
  END rw0_addr_in[6]
  PIN rw0_addr_in[7]
    DIRECTION INPUT ;
    USE SIGNAL ;
    SHAPE ABUTMENT ;
    PORT
      LAYER metal3 ;
      RECT 1461.270 442.085 1461.480 442.155 ;
    END
  END rw0_addr_in[7]
  PIN rw0_addr_in[8]
    DIRECTION INPUT ;
    USE SIGNAL ;
    SHAPE ABUTMENT ;
    PORT
      LAYER metal3 ;
      RECT 1461.270 469.665 1461.480 469.735 ;
    END
  END rw0_addr_in[8]
  PIN rw0_addr_in[9]
    DIRECTION INPUT ;
    USE SIGNAL ;
    SHAPE ABUTMENT ;
    PORT
      LAYER metal3 ;
      RECT 1461.270 497.245 1461.480 497.315 ;
    END
  END rw0_addr_in[9]
  PIN rw0_addr_in[10]
    DIRECTION INPUT ;
    USE SIGNAL ;
    SHAPE ABUTMENT ;
    PORT
      LAYER metal3 ;
      RECT 1461.270 524.825 1461.480 524.895 ;
    END
  END rw0_addr_in[10]
  PIN rw0_addr_in[11]
    DIRECTION INPUT ;
    USE SIGNAL ;
    SHAPE ABUTMENT ;
    PORT
      LAYER metal3 ;
      RECT 1461.270 552.405 1461.480 552.475 ;
    END
  END rw0_addr_in[11]
  PIN rw0_addr_in[12]
    DIRECTION INPUT ;
    USE SIGNAL ;
    SHAPE ABUTMENT ;
    PORT
      LAYER metal3 ;
      RECT 1461.270 579.985 1461.480 580.055 ;
    END
  END rw0_addr_in[12]
  PIN rw0_addr_in[13]
    DIRECTION INPUT ;
    USE SIGNAL ;
    SHAPE ABUTMENT ;
    PORT
      LAYER metal3 ;
      RECT 1461.270 607.565 1461.480 607.635 ;
    END
  END rw0_addr_in[13]
  PIN rw0_we_in
    DIRECTION INPUT ;
    USE SIGNAL ;
    SHAPE ABUTMENT ;
    PORT
      LAYER metal2 ;
      RECT 1332.625 636.790 1332.695 637.000 ;
    END
  END rw0_we_in
  PIN rw0_ce_in
    DIRECTION INPUT ;
    USE SIGNAL ;
    SHAPE ABUTMENT ;
    PORT
      LAYER metal2 ;
      RECT 1374.235 636.790 1374.305 637.000 ;
    END
  END rw0_ce_in
  PIN rw0_clk
    DIRECTION INPUT ;
    USE SIGNAL ;
    SHAPE ABUTMENT ;
    PORT
      LAYER metal2 ;
      RECT 1415.845 636.790 1415.915 637.000 ;
    END
  END rw0_clk
  PIN VSS
    DIRECTION INOUT ;
    USE GROUND ;
    PORT
      LAYER metal4 ;
      RECT 1.000 0.840 1.280 636.160 ;
      RECT 3.240 0.840 3.520 636.160 ;
      RECT 5.480 0.840 5.760 636.160 ;
      RECT 7.720 0.840 8.000 636.160 ;
      RECT 9.960 0.840 10.240 636.160 ;
      RECT 12.200 0.840 12.480 636.160 ;
      RECT 14.440 0.840 14.720 636.160 ;
      RECT 16.680 0.840 16.960 636.160 ;
      RECT 18.920 0.840 19.200 636.160 ;
      RECT 21.160 0.840 21.440 636.160 ;
      RECT 23.400 0.840 23.680 636.160 ;
      RECT 25.640 0.840 25.920 636.160 ;
      RECT 27.880 0.840 28.160 636.160 ;
      RECT 30.120 0.840 30.400 636.160 ;
      RECT 32.360 0.840 32.640 636.160 ;
      RECT 34.600 0.840 34.880 636.160 ;
      RECT 36.840 0.840 37.120 636.160 ;
      RECT 39.080 0.840 39.360 636.160 ;
      RECT 41.320 0.840 41.600 636.160 ;
      RECT 43.560 0.840 43.840 636.160 ;
      RECT 45.800 0.840 46.080 636.160 ;
      RECT 48.040 0.840 48.320 636.160 ;
      RECT 50.280 0.840 50.560 636.160 ;
      RECT 52.520 0.840 52.800 636.160 ;
      RECT 54.760 0.840 55.040 636.160 ;
      RECT 57.000 0.840 57.280 636.160 ;
      RECT 59.240 0.840 59.520 636.160 ;
      RECT 61.480 0.840 61.760 636.160 ;
      RECT 63.720 0.840 64.000 636.160 ;
      RECT 65.960 0.840 66.240 636.160 ;
      RECT 68.200 0.840 68.480 636.160 ;
      RECT 70.440 0.840 70.720 636.160 ;
      RECT 72.680 0.840 72.960 636.160 ;
      RECT 74.920 0.840 75.200 636.160 ;
      RECT 77.160 0.840 77.440 636.160 ;
      RECT 79.400 0.840 79.680 636.160 ;
      RECT 81.640 0.840 81.920 636.160 ;
      RECT 83.880 0.840 84.160 636.160 ;
      RECT 86.120 0.840 86.400 636.160 ;
      RECT 88.360 0.840 88.640 636.160 ;
      RECT 90.600 0.840 90.880 636.160 ;
      RECT 92.840 0.840 93.120 636.160 ;
      RECT 95.080 0.840 95.360 636.160 ;
      RECT 97.320 0.840 97.600 636.160 ;
      RECT 99.560 0.840 99.840 636.160 ;
      RECT 101.800 0.840 102.080 636.160 ;
      RECT 104.040 0.840 104.320 636.160 ;
      RECT 106.280 0.840 106.560 636.160 ;
      RECT 108.520 0.840 108.800 636.160 ;
      RECT 110.760 0.840 111.040 636.160 ;
      RECT 113.000 0.840 113.280 636.160 ;
      RECT 115.240 0.840 115.520 636.160 ;
      RECT 117.480 0.840 117.760 636.160 ;
      RECT 119.720 0.840 120.000 636.160 ;
      RECT 121.960 0.840 122.240 636.160 ;
      RECT 124.200 0.840 124.480 636.160 ;
      RECT 126.440 0.840 126.720 636.160 ;
      RECT 128.680 0.840 128.960 636.160 ;
      RECT 130.920 0.840 131.200 636.160 ;
      RECT 133.160 0.840 133.440 636.160 ;
      RECT 135.400 0.840 135.680 636.160 ;
      RECT 137.640 0.840 137.920 636.160 ;
      RECT 139.880 0.840 140.160 636.160 ;
      RECT 142.120 0.840 142.400 636.160 ;
      RECT 144.360 0.840 144.640 636.160 ;
      RECT 146.600 0.840 146.880 636.160 ;
      RECT 148.840 0.840 149.120 636.160 ;
      RECT 151.080 0.840 151.360 636.160 ;
      RECT 153.320 0.840 153.600 636.160 ;
      RECT 155.560 0.840 155.840 636.160 ;
      RECT 157.800 0.840 158.080 636.160 ;
      RECT 160.040 0.840 160.320 636.160 ;
      RECT 162.280 0.840 162.560 636.160 ;
      RECT 164.520 0.840 164.800 636.160 ;
      RECT 166.760 0.840 167.040 636.160 ;
      RECT 169.000 0.840 169.280 636.160 ;
      RECT 171.240 0.840 171.520 636.160 ;
      RECT 173.480 0.840 173.760 636.160 ;
      RECT 175.720 0.840 176.000 636.160 ;
      RECT 177.960 0.840 178.240 636.160 ;
      RECT 180.200 0.840 180.480 636.160 ;
      RECT 182.440 0.840 182.720 636.160 ;
      RECT 184.680 0.840 184.960 636.160 ;
      RECT 186.920 0.840 187.200 636.160 ;
      RECT 189.160 0.840 189.440 636.160 ;
      RECT 191.400 0.840 191.680 636.160 ;
      RECT 193.640 0.840 193.920 636.160 ;
      RECT 195.880 0.840 196.160 636.160 ;
      RECT 198.120 0.840 198.400 636.160 ;
      RECT 200.360 0.840 200.640 636.160 ;
      RECT 202.600 0.840 202.880 636.160 ;
      RECT 204.840 0.840 205.120 636.160 ;
      RECT 207.080 0.840 207.360 636.160 ;
      RECT 209.320 0.840 209.600 636.160 ;
      RECT 211.560 0.840 211.840 636.160 ;
      RECT 213.800 0.840 214.080 636.160 ;
      RECT 216.040 0.840 216.320 636.160 ;
      RECT 218.280 0.840 218.560 636.160 ;
      RECT 220.520 0.840 220.800 636.160 ;
      RECT 222.760 0.840 223.040 636.160 ;
      RECT 225.000 0.840 225.280 636.160 ;
      RECT 227.240 0.840 227.520 636.160 ;
      RECT 229.480 0.840 229.760 636.160 ;
      RECT 231.720 0.840 232.000 636.160 ;
      RECT 233.960 0.840 234.240 636.160 ;
      RECT 236.200 0.840 236.480 636.160 ;
      RECT 238.440 0.840 238.720 636.160 ;
      RECT 240.680 0.840 240.960 636.160 ;
      RECT 242.920 0.840 243.200 636.160 ;
      RECT 245.160 0.840 245.440 636.160 ;
      RECT 247.400 0.840 247.680 636.160 ;
      RECT 249.640 0.840 249.920 636.160 ;
      RECT 251.880 0.840 252.160 636.160 ;
      RECT 254.120 0.840 254.400 636.160 ;
      RECT 256.360 0.840 256.640 636.160 ;
      RECT 258.600 0.840 258.880 636.160 ;
      RECT 260.840 0.840 261.120 636.160 ;
      RECT 263.080 0.840 263.360 636.160 ;
      RECT 265.320 0.840 265.600 636.160 ;
      RECT 267.560 0.840 267.840 636.160 ;
      RECT 269.800 0.840 270.080 636.160 ;
      RECT 272.040 0.840 272.320 636.160 ;
      RECT 274.280 0.840 274.560 636.160 ;
      RECT 276.520 0.840 276.800 636.160 ;
      RECT 278.760 0.840 279.040 636.160 ;
      RECT 281.000 0.840 281.280 636.160 ;
      RECT 283.240 0.840 283.520 636.160 ;
      RECT 285.480 0.840 285.760 636.160 ;
      RECT 287.720 0.840 288.000 636.160 ;
      RECT 289.960 0.840 290.240 636.160 ;
      RECT 292.200 0.840 292.480 636.160 ;
      RECT 294.440 0.840 294.720 636.160 ;
      RECT 296.680 0.840 296.960 636.160 ;
      RECT 298.920 0.840 299.200 636.160 ;
      RECT 301.160 0.840 301.440 636.160 ;
      RECT 303.400 0.840 303.680 636.160 ;
      RECT 305.640 0.840 305.920 636.160 ;
      RECT 307.880 0.840 308.160 636.160 ;
      RECT 310.120 0.840 310.400 636.160 ;
      RECT 312.360 0.840 312.640 636.160 ;
      RECT 314.600 0.840 314.880 636.160 ;
      RECT 316.840 0.840 317.120 636.160 ;
      RECT 319.080 0.840 319.360 636.160 ;
      RECT 321.320 0.840 321.600 636.160 ;
      RECT 323.560 0.840 323.840 636.160 ;
      RECT 325.800 0.840 326.080 636.160 ;
      RECT 328.040 0.840 328.320 636.160 ;
      RECT 330.280 0.840 330.560 636.160 ;
      RECT 332.520 0.840 332.800 636.160 ;
      RECT 334.760 0.840 335.040 636.160 ;
      RECT 337.000 0.840 337.280 636.160 ;
      RECT 339.240 0.840 339.520 636.160 ;
      RECT 341.480 0.840 341.760 636.160 ;
      RECT 343.720 0.840 344.000 636.160 ;
      RECT 345.960 0.840 346.240 636.160 ;
      RECT 348.200 0.840 348.480 636.160 ;
      RECT 350.440 0.840 350.720 636.160 ;
      RECT 352.680 0.840 352.960 636.160 ;
      RECT 354.920 0.840 355.200 636.160 ;
      RECT 357.160 0.840 357.440 636.160 ;
      RECT 359.400 0.840 359.680 636.160 ;
      RECT 361.640 0.840 361.920 636.160 ;
      RECT 363.880 0.840 364.160 636.160 ;
      RECT 366.120 0.840 366.400 636.160 ;
      RECT 368.360 0.840 368.640 636.160 ;
      RECT 370.600 0.840 370.880 636.160 ;
      RECT 372.840 0.840 373.120 636.160 ;
      RECT 375.080 0.840 375.360 636.160 ;
      RECT 377.320 0.840 377.600 636.160 ;
      RECT 379.560 0.840 379.840 636.160 ;
      RECT 381.800 0.840 382.080 636.160 ;
      RECT 384.040 0.840 384.320 636.160 ;
      RECT 386.280 0.840 386.560 636.160 ;
      RECT 388.520 0.840 388.800 636.160 ;
      RECT 390.760 0.840 391.040 636.160 ;
      RECT 393.000 0.840 393.280 636.160 ;
      RECT 395.240 0.840 395.520 636.160 ;
      RECT 397.480 0.840 397.760 636.160 ;
      RECT 399.720 0.840 400.000 636.160 ;
      RECT 401.960 0.840 402.240 636.160 ;
      RECT 404.200 0.840 404.480 636.160 ;
      RECT 406.440 0.840 406.720 636.160 ;
      RECT 408.680 0.840 408.960 636.160 ;
      RECT 410.920 0.840 411.200 636.160 ;
      RECT 413.160 0.840 413.440 636.160 ;
      RECT 415.400 0.840 415.680 636.160 ;
      RECT 417.640 0.840 417.920 636.160 ;
      RECT 419.880 0.840 420.160 636.160 ;
      RECT 422.120 0.840 422.400 636.160 ;
      RECT 424.360 0.840 424.640 636.160 ;
      RECT 426.600 0.840 426.880 636.160 ;
      RECT 428.840 0.840 429.120 636.160 ;
      RECT 431.080 0.840 431.360 636.160 ;
      RECT 433.320 0.840 433.600 636.160 ;
      RECT 435.560 0.840 435.840 636.160 ;
      RECT 437.800 0.840 438.080 636.160 ;
      RECT 440.040 0.840 440.320 636.160 ;
      RECT 442.280 0.840 442.560 636.160 ;
      RECT 444.520 0.840 444.800 636.160 ;
      RECT 446.760 0.840 447.040 636.160 ;
      RECT 449.000 0.840 449.280 636.160 ;
      RECT 451.240 0.840 451.520 636.160 ;
      RECT 453.480 0.840 453.760 636.160 ;
      RECT 455.720 0.840 456.000 636.160 ;
      RECT 457.960 0.840 458.240 636.160 ;
      RECT 460.200 0.840 460.480 636.160 ;
      RECT 462.440 0.840 462.720 636.160 ;
      RECT 464.680 0.840 464.960 636.160 ;
      RECT 466.920 0.840 467.200 636.160 ;
      RECT 469.160 0.840 469.440 636.160 ;
      RECT 471.400 0.840 471.680 636.160 ;
      RECT 473.640 0.840 473.920 636.160 ;
      RECT 475.880 0.840 476.160 636.160 ;
      RECT 478.120 0.840 478.400 636.160 ;
      RECT 480.360 0.840 480.640 636.160 ;
      RECT 482.600 0.840 482.880 636.160 ;
      RECT 484.840 0.840 485.120 636.160 ;
      RECT 487.080 0.840 487.360 636.160 ;
      RECT 489.320 0.840 489.600 636.160 ;
      RECT 491.560 0.840 491.840 636.160 ;
      RECT 493.800 0.840 494.080 636.160 ;
      RECT 496.040 0.840 496.320 636.160 ;
      RECT 498.280 0.840 498.560 636.160 ;
      RECT 500.520 0.840 500.800 636.160 ;
      RECT 502.760 0.840 503.040 636.160 ;
      RECT 505.000 0.840 505.280 636.160 ;
      RECT 507.240 0.840 507.520 636.160 ;
      RECT 509.480 0.840 509.760 636.160 ;
      RECT 511.720 0.840 512.000 636.160 ;
      RECT 513.960 0.840 514.240 636.160 ;
      RECT 516.200 0.840 516.480 636.160 ;
      RECT 518.440 0.840 518.720 636.160 ;
      RECT 520.680 0.840 520.960 636.160 ;
      RECT 522.920 0.840 523.200 636.160 ;
      RECT 525.160 0.840 525.440 636.160 ;
      RECT 527.400 0.840 527.680 636.160 ;
      RECT 529.640 0.840 529.920 636.160 ;
      RECT 531.880 0.840 532.160 636.160 ;
      RECT 534.120 0.840 534.400 636.160 ;
      RECT 536.360 0.840 536.640 636.160 ;
      RECT 538.600 0.840 538.880 636.160 ;
      RECT 540.840 0.840 541.120 636.160 ;
      RECT 543.080 0.840 543.360 636.160 ;
      RECT 545.320 0.840 545.600 636.160 ;
      RECT 547.560 0.840 547.840 636.160 ;
      RECT 549.800 0.840 550.080 636.160 ;
      RECT 552.040 0.840 552.320 636.160 ;
      RECT 554.280 0.840 554.560 636.160 ;
      RECT 556.520 0.840 556.800 636.160 ;
      RECT 558.760 0.840 559.040 636.160 ;
      RECT 561.000 0.840 561.280 636.160 ;
      RECT 563.240 0.840 563.520 636.160 ;
      RECT 565.480 0.840 565.760 636.160 ;
      RECT 567.720 0.840 568.000 636.160 ;
      RECT 569.960 0.840 570.240 636.160 ;
      RECT 572.200 0.840 572.480 636.160 ;
      RECT 574.440 0.840 574.720 636.160 ;
      RECT 576.680 0.840 576.960 636.160 ;
      RECT 578.920 0.840 579.200 636.160 ;
      RECT 581.160 0.840 581.440 636.160 ;
      RECT 583.400 0.840 583.680 636.160 ;
      RECT 585.640 0.840 585.920 636.160 ;
      RECT 587.880 0.840 588.160 636.160 ;
      RECT 590.120 0.840 590.400 636.160 ;
      RECT 592.360 0.840 592.640 636.160 ;
      RECT 594.600 0.840 594.880 636.160 ;
      RECT 596.840 0.840 597.120 636.160 ;
      RECT 599.080 0.840 599.360 636.160 ;
      RECT 601.320 0.840 601.600 636.160 ;
      RECT 603.560 0.840 603.840 636.160 ;
      RECT 605.800 0.840 606.080 636.160 ;
      RECT 608.040 0.840 608.320 636.160 ;
      RECT 610.280 0.840 610.560 636.160 ;
      RECT 612.520 0.840 612.800 636.160 ;
      RECT 614.760 0.840 615.040 636.160 ;
      RECT 617.000 0.840 617.280 636.160 ;
      RECT 619.240 0.840 619.520 636.160 ;
      RECT 621.480 0.840 621.760 636.160 ;
      RECT 623.720 0.840 624.000 636.160 ;
      RECT 625.960 0.840 626.240 636.160 ;
      RECT 628.200 0.840 628.480 636.160 ;
      RECT 630.440 0.840 630.720 636.160 ;
      RECT 632.680 0.840 632.960 636.160 ;
      RECT 634.920 0.840 635.200 636.160 ;
      RECT 637.160 0.840 637.440 636.160 ;
      RECT 639.400 0.840 639.680 636.160 ;
      RECT 641.640 0.840 641.920 636.160 ;
      RECT 643.880 0.840 644.160 636.160 ;
      RECT 646.120 0.840 646.400 636.160 ;
      RECT 648.360 0.840 648.640 636.160 ;
      RECT 650.600 0.840 650.880 636.160 ;
      RECT 652.840 0.840 653.120 636.160 ;
      RECT 655.080 0.840 655.360 636.160 ;
      RECT 657.320 0.840 657.600 636.160 ;
      RECT 659.560 0.840 659.840 636.160 ;
      RECT 661.800 0.840 662.080 636.160 ;
      RECT 664.040 0.840 664.320 636.160 ;
      RECT 666.280 0.840 666.560 636.160 ;
      RECT 668.520 0.840 668.800 636.160 ;
      RECT 670.760 0.840 671.040 636.160 ;
      RECT 673.000 0.840 673.280 636.160 ;
      RECT 675.240 0.840 675.520 636.160 ;
      RECT 677.480 0.840 677.760 636.160 ;
      RECT 679.720 0.840 680.000 636.160 ;
      RECT 681.960 0.840 682.240 636.160 ;
      RECT 684.200 0.840 684.480 636.160 ;
      RECT 686.440 0.840 686.720 636.160 ;
      RECT 688.680 0.840 688.960 636.160 ;
      RECT 690.920 0.840 691.200 636.160 ;
      RECT 693.160 0.840 693.440 636.160 ;
      RECT 695.400 0.840 695.680 636.160 ;
      RECT 697.640 0.840 697.920 636.160 ;
      RECT 699.880 0.840 700.160 636.160 ;
      RECT 702.120 0.840 702.400 636.160 ;
      RECT 704.360 0.840 704.640 636.160 ;
      RECT 706.600 0.840 706.880 636.160 ;
      RECT 708.840 0.840 709.120 636.160 ;
      RECT 711.080 0.840 711.360 636.160 ;
      RECT 713.320 0.840 713.600 636.160 ;
      RECT 715.560 0.840 715.840 636.160 ;
      RECT 717.800 0.840 718.080 636.160 ;
      RECT 720.040 0.840 720.320 636.160 ;
      RECT 722.280 0.840 722.560 636.160 ;
      RECT 724.520 0.840 724.800 636.160 ;
      RECT 726.760 0.840 727.040 636.160 ;
      RECT 729.000 0.840 729.280 636.160 ;
      RECT 731.240 0.840 731.520 636.160 ;
      RECT 733.480 0.840 733.760 636.160 ;
      RECT 735.720 0.840 736.000 636.160 ;
      RECT 737.960 0.840 738.240 636.160 ;
      RECT 740.200 0.840 740.480 636.160 ;
      RECT 742.440 0.840 742.720 636.160 ;
      RECT 744.680 0.840 744.960 636.160 ;
      RECT 746.920 0.840 747.200 636.160 ;
      RECT 749.160 0.840 749.440 636.160 ;
      RECT 751.400 0.840 751.680 636.160 ;
      RECT 753.640 0.840 753.920 636.160 ;
      RECT 755.880 0.840 756.160 636.160 ;
      RECT 758.120 0.840 758.400 636.160 ;
      RECT 760.360 0.840 760.640 636.160 ;
      RECT 762.600 0.840 762.880 636.160 ;
      RECT 764.840 0.840 765.120 636.160 ;
      RECT 767.080 0.840 767.360 636.160 ;
      RECT 769.320 0.840 769.600 636.160 ;
      RECT 771.560 0.840 771.840 636.160 ;
      RECT 773.800 0.840 774.080 636.160 ;
      RECT 776.040 0.840 776.320 636.160 ;
      RECT 778.280 0.840 778.560 636.160 ;
      RECT 780.520 0.840 780.800 636.160 ;
      RECT 782.760 0.840 783.040 636.160 ;
      RECT 785.000 0.840 785.280 636.160 ;
      RECT 787.240 0.840 787.520 636.160 ;
      RECT 789.480 0.840 789.760 636.160 ;
      RECT 791.720 0.840 792.000 636.160 ;
      RECT 793.960 0.840 794.240 636.160 ;
      RECT 796.200 0.840 796.480 636.160 ;
      RECT 798.440 0.840 798.720 636.160 ;
      RECT 800.680 0.840 800.960 636.160 ;
      RECT 802.920 0.840 803.200 636.160 ;
      RECT 805.160 0.840 805.440 636.160 ;
      RECT 807.400 0.840 807.680 636.160 ;
      RECT 809.640 0.840 809.920 636.160 ;
      RECT 811.880 0.840 812.160 636.160 ;
      RECT 814.120 0.840 814.400 636.160 ;
      RECT 816.360 0.840 816.640 636.160 ;
      RECT 818.600 0.840 818.880 636.160 ;
      RECT 820.840 0.840 821.120 636.160 ;
      RECT 823.080 0.840 823.360 636.160 ;
      RECT 825.320 0.840 825.600 636.160 ;
      RECT 827.560 0.840 827.840 636.160 ;
      RECT 829.800 0.840 830.080 636.160 ;
      RECT 832.040 0.840 832.320 636.160 ;
      RECT 834.280 0.840 834.560 636.160 ;
      RECT 836.520 0.840 836.800 636.160 ;
      RECT 838.760 0.840 839.040 636.160 ;
      RECT 841.000 0.840 841.280 636.160 ;
      RECT 843.240 0.840 843.520 636.160 ;
      RECT 845.480 0.840 845.760 636.160 ;
      RECT 847.720 0.840 848.000 636.160 ;
      RECT 849.960 0.840 850.240 636.160 ;
      RECT 852.200 0.840 852.480 636.160 ;
      RECT 854.440 0.840 854.720 636.160 ;
      RECT 856.680 0.840 856.960 636.160 ;
      RECT 858.920 0.840 859.200 636.160 ;
      RECT 861.160 0.840 861.440 636.160 ;
      RECT 863.400 0.840 863.680 636.160 ;
      RECT 865.640 0.840 865.920 636.160 ;
      RECT 867.880 0.840 868.160 636.160 ;
      RECT 870.120 0.840 870.400 636.160 ;
      RECT 872.360 0.840 872.640 636.160 ;
      RECT 874.600 0.840 874.880 636.160 ;
      RECT 876.840 0.840 877.120 636.160 ;
      RECT 879.080 0.840 879.360 636.160 ;
      RECT 881.320 0.840 881.600 636.160 ;
      RECT 883.560 0.840 883.840 636.160 ;
      RECT 885.800 0.840 886.080 636.160 ;
      RECT 888.040 0.840 888.320 636.160 ;
      RECT 890.280 0.840 890.560 636.160 ;
      RECT 892.520 0.840 892.800 636.160 ;
      RECT 894.760 0.840 895.040 636.160 ;
      RECT 897.000 0.840 897.280 636.160 ;
      RECT 899.240 0.840 899.520 636.160 ;
      RECT 901.480 0.840 901.760 636.160 ;
      RECT 903.720 0.840 904.000 636.160 ;
      RECT 905.960 0.840 906.240 636.160 ;
      RECT 908.200 0.840 908.480 636.160 ;
      RECT 910.440 0.840 910.720 636.160 ;
      RECT 912.680 0.840 912.960 636.160 ;
      RECT 914.920 0.840 915.200 636.160 ;
      RECT 917.160 0.840 917.440 636.160 ;
      RECT 919.400 0.840 919.680 636.160 ;
      RECT 921.640 0.840 921.920 636.160 ;
      RECT 923.880 0.840 924.160 636.160 ;
      RECT 926.120 0.840 926.400 636.160 ;
      RECT 928.360 0.840 928.640 636.160 ;
      RECT 930.600 0.840 930.880 636.160 ;
      RECT 932.840 0.840 933.120 636.160 ;
      RECT 935.080 0.840 935.360 636.160 ;
      RECT 937.320 0.840 937.600 636.160 ;
      RECT 939.560 0.840 939.840 636.160 ;
      RECT 941.800 0.840 942.080 636.160 ;
      RECT 944.040 0.840 944.320 636.160 ;
      RECT 946.280 0.840 946.560 636.160 ;
      RECT 948.520 0.840 948.800 636.160 ;
      RECT 950.760 0.840 951.040 636.160 ;
      RECT 953.000 0.840 953.280 636.160 ;
      RECT 955.240 0.840 955.520 636.160 ;
      RECT 957.480 0.840 957.760 636.160 ;
      RECT 959.720 0.840 960.000 636.160 ;
      RECT 961.960 0.840 962.240 636.160 ;
      RECT 964.200 0.840 964.480 636.160 ;
      RECT 966.440 0.840 966.720 636.160 ;
      RECT 968.680 0.840 968.960 636.160 ;
      RECT 970.920 0.840 971.200 636.160 ;
      RECT 973.160 0.840 973.440 636.160 ;
      RECT 975.400 0.840 975.680 636.160 ;
      RECT 977.640 0.840 977.920 636.160 ;
      RECT 979.880 0.840 980.160 636.160 ;
      RECT 982.120 0.840 982.400 636.160 ;
      RECT 984.360 0.840 984.640 636.160 ;
      RECT 986.600 0.840 986.880 636.160 ;
      RECT 988.840 0.840 989.120 636.160 ;
      RECT 991.080 0.840 991.360 636.160 ;
      RECT 993.320 0.840 993.600 636.160 ;
      RECT 995.560 0.840 995.840 636.160 ;
      RECT 997.800 0.840 998.080 636.160 ;
      RECT 1000.040 0.840 1000.320 636.160 ;
      RECT 1002.280 0.840 1002.560 636.160 ;
      RECT 1004.520 0.840 1004.800 636.160 ;
      RECT 1006.760 0.840 1007.040 636.160 ;
      RECT 1009.000 0.840 1009.280 636.160 ;
      RECT 1011.240 0.840 1011.520 636.160 ;
      RECT 1013.480 0.840 1013.760 636.160 ;
      RECT 1015.720 0.840 1016.000 636.160 ;
      RECT 1017.960 0.840 1018.240 636.160 ;
      RECT 1020.200 0.840 1020.480 636.160 ;
      RECT 1022.440 0.840 1022.720 636.160 ;
      RECT 1024.680 0.840 1024.960 636.160 ;
      RECT 1026.920 0.840 1027.200 636.160 ;
      RECT 1029.160 0.840 1029.440 636.160 ;
      RECT 1031.400 0.840 1031.680 636.160 ;
      RECT 1033.640 0.840 1033.920 636.160 ;
      RECT 1035.880 0.840 1036.160 636.160 ;
      RECT 1038.120 0.840 1038.400 636.160 ;
      RECT 1040.360 0.840 1040.640 636.160 ;
      RECT 1042.600 0.840 1042.880 636.160 ;
      RECT 1044.840 0.840 1045.120 636.160 ;
      RECT 1047.080 0.840 1047.360 636.160 ;
      RECT 1049.320 0.840 1049.600 636.160 ;
      RECT 1051.560 0.840 1051.840 636.160 ;
      RECT 1053.800 0.840 1054.080 636.160 ;
      RECT 1056.040 0.840 1056.320 636.160 ;
      RECT 1058.280 0.840 1058.560 636.160 ;
      RECT 1060.520 0.840 1060.800 636.160 ;
      RECT 1062.760 0.840 1063.040 636.160 ;
      RECT 1065.000 0.840 1065.280 636.160 ;
      RECT 1067.240 0.840 1067.520 636.160 ;
      RECT 1069.480 0.840 1069.760 636.160 ;
      RECT 1071.720 0.840 1072.000 636.160 ;
      RECT 1073.960 0.840 1074.240 636.160 ;
      RECT 1076.200 0.840 1076.480 636.160 ;
      RECT 1078.440 0.840 1078.720 636.160 ;
      RECT 1080.680 0.840 1080.960 636.160 ;
      RECT 1082.920 0.840 1083.200 636.160 ;
      RECT 1085.160 0.840 1085.440 636.160 ;
      RECT 1087.400 0.840 1087.680 636.160 ;
      RECT 1089.640 0.840 1089.920 636.160 ;
      RECT 1091.880 0.840 1092.160 636.160 ;
      RECT 1094.120 0.840 1094.400 636.160 ;
      RECT 1096.360 0.840 1096.640 636.160 ;
      RECT 1098.600 0.840 1098.880 636.160 ;
      RECT 1100.840 0.840 1101.120 636.160 ;
      RECT 1103.080 0.840 1103.360 636.160 ;
      RECT 1105.320 0.840 1105.600 636.160 ;
      RECT 1107.560 0.840 1107.840 636.160 ;
      RECT 1109.800 0.840 1110.080 636.160 ;
      RECT 1112.040 0.840 1112.320 636.160 ;
      RECT 1114.280 0.840 1114.560 636.160 ;
      RECT 1116.520 0.840 1116.800 636.160 ;
      RECT 1118.760 0.840 1119.040 636.160 ;
      RECT 1121.000 0.840 1121.280 636.160 ;
      RECT 1123.240 0.840 1123.520 636.160 ;
      RECT 1125.480 0.840 1125.760 636.160 ;
      RECT 1127.720 0.840 1128.000 636.160 ;
      RECT 1129.960 0.840 1130.240 636.160 ;
      RECT 1132.200 0.840 1132.480 636.160 ;
      RECT 1134.440 0.840 1134.720 636.160 ;
      RECT 1136.680 0.840 1136.960 636.160 ;
      RECT 1138.920 0.840 1139.200 636.160 ;
      RECT 1141.160 0.840 1141.440 636.160 ;
      RECT 1143.400 0.840 1143.680 636.160 ;
      RECT 1145.640 0.840 1145.920 636.160 ;
      RECT 1147.880 0.840 1148.160 636.160 ;
      RECT 1150.120 0.840 1150.400 636.160 ;
      RECT 1152.360 0.840 1152.640 636.160 ;
      RECT 1154.600 0.840 1154.880 636.160 ;
      RECT 1156.840 0.840 1157.120 636.160 ;
      RECT 1159.080 0.840 1159.360 636.160 ;
      RECT 1161.320 0.840 1161.600 636.160 ;
      RECT 1163.560 0.840 1163.840 636.160 ;
      RECT 1165.800 0.840 1166.080 636.160 ;
      RECT 1168.040 0.840 1168.320 636.160 ;
      RECT 1170.280 0.840 1170.560 636.160 ;
      RECT 1172.520 0.840 1172.800 636.160 ;
      RECT 1174.760 0.840 1175.040 636.160 ;
      RECT 1177.000 0.840 1177.280 636.160 ;
      RECT 1179.240 0.840 1179.520 636.160 ;
      RECT 1181.480 0.840 1181.760 636.160 ;
      RECT 1183.720 0.840 1184.000 636.160 ;
      RECT 1185.960 0.840 1186.240 636.160 ;
      RECT 1188.200 0.840 1188.480 636.160 ;
      RECT 1190.440 0.840 1190.720 636.160 ;
      RECT 1192.680 0.840 1192.960 636.160 ;
      RECT 1194.920 0.840 1195.200 636.160 ;
      RECT 1197.160 0.840 1197.440 636.160 ;
      RECT 1199.400 0.840 1199.680 636.160 ;
      RECT 1201.640 0.840 1201.920 636.160 ;
      RECT 1203.880 0.840 1204.160 636.160 ;
      RECT 1206.120 0.840 1206.400 636.160 ;
      RECT 1208.360 0.840 1208.640 636.160 ;
      RECT 1210.600 0.840 1210.880 636.160 ;
      RECT 1212.840 0.840 1213.120 636.160 ;
      RECT 1215.080 0.840 1215.360 636.160 ;
      RECT 1217.320 0.840 1217.600 636.160 ;
      RECT 1219.560 0.840 1219.840 636.160 ;
      RECT 1221.800 0.840 1222.080 636.160 ;
      RECT 1224.040 0.840 1224.320 636.160 ;
      RECT 1226.280 0.840 1226.560 636.160 ;
      RECT 1228.520 0.840 1228.800 636.160 ;
      RECT 1230.760 0.840 1231.040 636.160 ;
      RECT 1233.000 0.840 1233.280 636.160 ;
      RECT 1235.240 0.840 1235.520 636.160 ;
      RECT 1237.480 0.840 1237.760 636.160 ;
      RECT 1239.720 0.840 1240.000 636.160 ;
      RECT 1241.960 0.840 1242.240 636.160 ;
      RECT 1244.200 0.840 1244.480 636.160 ;
      RECT 1246.440 0.840 1246.720 636.160 ;
      RECT 1248.680 0.840 1248.960 636.160 ;
      RECT 1250.920 0.840 1251.200 636.160 ;
      RECT 1253.160 0.840 1253.440 636.160 ;
      RECT 1255.400 0.840 1255.680 636.160 ;
      RECT 1257.640 0.840 1257.920 636.160 ;
      RECT 1259.880 0.840 1260.160 636.160 ;
      RECT 1262.120 0.840 1262.400 636.160 ;
      RECT 1264.360 0.840 1264.640 636.160 ;
      RECT 1266.600 0.840 1266.880 636.160 ;
      RECT 1268.840 0.840 1269.120 636.160 ;
      RECT 1271.080 0.840 1271.360 636.160 ;
      RECT 1273.320 0.840 1273.600 636.160 ;
      RECT 1275.560 0.840 1275.840 636.160 ;
      RECT 1277.800 0.840 1278.080 636.160 ;
      RECT 1280.040 0.840 1280.320 636.160 ;
      RECT 1282.280 0.840 1282.560 636.160 ;
      RECT 1284.520 0.840 1284.800 636.160 ;
      RECT 1286.760 0.840 1287.040 636.160 ;
      RECT 1289.000 0.840 1289.280 636.160 ;
      RECT 1291.240 0.840 1291.520 636.160 ;
      RECT 1293.480 0.840 1293.760 636.160 ;
      RECT 1295.720 0.840 1296.000 636.160 ;
      RECT 1297.960 0.840 1298.240 636.160 ;
      RECT 1300.200 0.840 1300.480 636.160 ;
      RECT 1302.440 0.840 1302.720 636.160 ;
      RECT 1304.680 0.840 1304.960 636.160 ;
      RECT 1306.920 0.840 1307.200 636.160 ;
      RECT 1309.160 0.840 1309.440 636.160 ;
      RECT 1311.400 0.840 1311.680 636.160 ;
      RECT 1313.640 0.840 1313.920 636.160 ;
      RECT 1315.880 0.840 1316.160 636.160 ;
      RECT 1318.120 0.840 1318.400 636.160 ;
      RECT 1320.360 0.840 1320.640 636.160 ;
      RECT 1322.600 0.840 1322.880 636.160 ;
      RECT 1324.840 0.840 1325.120 636.160 ;
      RECT 1327.080 0.840 1327.360 636.160 ;
      RECT 1329.320 0.840 1329.600 636.160 ;
      RECT 1331.560 0.840 1331.840 636.160 ;
      RECT 1333.800 0.840 1334.080 636.160 ;
      RECT 1336.040 0.840 1336.320 636.160 ;
      RECT 1338.280 0.840 1338.560 636.160 ;
      RECT 1340.520 0.840 1340.800 636.160 ;
      RECT 1342.760 0.840 1343.040 636.160 ;
      RECT 1345.000 0.840 1345.280 636.160 ;
      RECT 1347.240 0.840 1347.520 636.160 ;
      RECT 1349.480 0.840 1349.760 636.160 ;
      RECT 1351.720 0.840 1352.000 636.160 ;
      RECT 1353.960 0.840 1354.240 636.160 ;
      RECT 1356.200 0.840 1356.480 636.160 ;
      RECT 1358.440 0.840 1358.720 636.160 ;
      RECT 1360.680 0.840 1360.960 636.160 ;
      RECT 1362.920 0.840 1363.200 636.160 ;
      RECT 1365.160 0.840 1365.440 636.160 ;
      RECT 1367.400 0.840 1367.680 636.160 ;
      RECT 1369.640 0.840 1369.920 636.160 ;
      RECT 1371.880 0.840 1372.160 636.160 ;
      RECT 1374.120 0.840 1374.400 636.160 ;
      RECT 1376.360 0.840 1376.640 636.160 ;
      RECT 1378.600 0.840 1378.880 636.160 ;
      RECT 1380.840 0.840 1381.120 636.160 ;
      RECT 1383.080 0.840 1383.360 636.160 ;
      RECT 1385.320 0.840 1385.600 636.160 ;
      RECT 1387.560 0.840 1387.840 636.160 ;
      RECT 1389.800 0.840 1390.080 636.160 ;
      RECT 1392.040 0.840 1392.320 636.160 ;
      RECT 1394.280 0.840 1394.560 636.160 ;
      RECT 1396.520 0.840 1396.800 636.160 ;
      RECT 1398.760 0.840 1399.040 636.160 ;
      RECT 1401.000 0.840 1401.280 636.160 ;
      RECT 1403.240 0.840 1403.520 636.160 ;
      RECT 1405.480 0.840 1405.760 636.160 ;
      RECT 1407.720 0.840 1408.000 636.160 ;
      RECT 1409.960 0.840 1410.240 636.160 ;
      RECT 1412.200 0.840 1412.480 636.160 ;
      RECT 1414.440 0.840 1414.720 636.160 ;
      RECT 1416.680 0.840 1416.960 636.160 ;
      RECT 1418.920 0.840 1419.200 636.160 ;
      RECT 1421.160 0.840 1421.440 636.160 ;
      RECT 1423.400 0.840 1423.680 636.160 ;
      RECT 1425.640 0.840 1425.920 636.160 ;
      RECT 1427.880 0.840 1428.160 636.160 ;
      RECT 1430.120 0.840 1430.400 636.160 ;
      RECT 1432.360 0.840 1432.640 636.160 ;
      RECT 1434.600 0.840 1434.880 636.160 ;
      RECT 1436.840 0.840 1437.120 636.160 ;
      RECT 1439.080 0.840 1439.360 636.160 ;
      RECT 1441.320 0.840 1441.600 636.160 ;
      RECT 1443.560 0.840 1443.840 636.160 ;
      RECT 1445.800 0.840 1446.080 636.160 ;
      RECT 1448.040 0.840 1448.320 636.160 ;
      RECT 1450.280 0.840 1450.560 636.160 ;
      RECT 1452.520 0.840 1452.800 636.160 ;
      RECT 1454.760 0.840 1455.040 636.160 ;
      RECT 1457.000 0.840 1457.280 636.160 ;
      RECT 1459.240 0.840 1459.520 636.160 ;
    END
  END VSS
  PIN VDD
    DIRECTION INOUT ;
    USE POWER ;
    PORT
      LAYER metal4 ;
      RECT 2.120 0.840 2.400 636.160 ;
      RECT 4.360 0.840 4.640 636.160 ;
      RECT 6.600 0.840 6.880 636.160 ;
      RECT 8.840 0.840 9.120 636.160 ;
      RECT 11.080 0.840 11.360 636.160 ;
      RECT 13.320 0.840 13.600 636.160 ;
      RECT 15.560 0.840 15.840 636.160 ;
      RECT 17.800 0.840 18.080 636.160 ;
      RECT 20.040 0.840 20.320 636.160 ;
      RECT 22.280 0.840 22.560 636.160 ;
      RECT 24.520 0.840 24.800 636.160 ;
      RECT 26.760 0.840 27.040 636.160 ;
      RECT 29.000 0.840 29.280 636.160 ;
      RECT 31.240 0.840 31.520 636.160 ;
      RECT 33.480 0.840 33.760 636.160 ;
      RECT 35.720 0.840 36.000 636.160 ;
      RECT 37.960 0.840 38.240 636.160 ;
      RECT 40.200 0.840 40.480 636.160 ;
      RECT 42.440 0.840 42.720 636.160 ;
      RECT 44.680 0.840 44.960 636.160 ;
      RECT 46.920 0.840 47.200 636.160 ;
      RECT 49.160 0.840 49.440 636.160 ;
      RECT 51.400 0.840 51.680 636.160 ;
      RECT 53.640 0.840 53.920 636.160 ;
      RECT 55.880 0.840 56.160 636.160 ;
      RECT 58.120 0.840 58.400 636.160 ;
      RECT 60.360 0.840 60.640 636.160 ;
      RECT 62.600 0.840 62.880 636.160 ;
      RECT 64.840 0.840 65.120 636.160 ;
      RECT 67.080 0.840 67.360 636.160 ;
      RECT 69.320 0.840 69.600 636.160 ;
      RECT 71.560 0.840 71.840 636.160 ;
      RECT 73.800 0.840 74.080 636.160 ;
      RECT 76.040 0.840 76.320 636.160 ;
      RECT 78.280 0.840 78.560 636.160 ;
      RECT 80.520 0.840 80.800 636.160 ;
      RECT 82.760 0.840 83.040 636.160 ;
      RECT 85.000 0.840 85.280 636.160 ;
      RECT 87.240 0.840 87.520 636.160 ;
      RECT 89.480 0.840 89.760 636.160 ;
      RECT 91.720 0.840 92.000 636.160 ;
      RECT 93.960 0.840 94.240 636.160 ;
      RECT 96.200 0.840 96.480 636.160 ;
      RECT 98.440 0.840 98.720 636.160 ;
      RECT 100.680 0.840 100.960 636.160 ;
      RECT 102.920 0.840 103.200 636.160 ;
      RECT 105.160 0.840 105.440 636.160 ;
      RECT 107.400 0.840 107.680 636.160 ;
      RECT 109.640 0.840 109.920 636.160 ;
      RECT 111.880 0.840 112.160 636.160 ;
      RECT 114.120 0.840 114.400 636.160 ;
      RECT 116.360 0.840 116.640 636.160 ;
      RECT 118.600 0.840 118.880 636.160 ;
      RECT 120.840 0.840 121.120 636.160 ;
      RECT 123.080 0.840 123.360 636.160 ;
      RECT 125.320 0.840 125.600 636.160 ;
      RECT 127.560 0.840 127.840 636.160 ;
      RECT 129.800 0.840 130.080 636.160 ;
      RECT 132.040 0.840 132.320 636.160 ;
      RECT 134.280 0.840 134.560 636.160 ;
      RECT 136.520 0.840 136.800 636.160 ;
      RECT 138.760 0.840 139.040 636.160 ;
      RECT 141.000 0.840 141.280 636.160 ;
      RECT 143.240 0.840 143.520 636.160 ;
      RECT 145.480 0.840 145.760 636.160 ;
      RECT 147.720 0.840 148.000 636.160 ;
      RECT 149.960 0.840 150.240 636.160 ;
      RECT 152.200 0.840 152.480 636.160 ;
      RECT 154.440 0.840 154.720 636.160 ;
      RECT 156.680 0.840 156.960 636.160 ;
      RECT 158.920 0.840 159.200 636.160 ;
      RECT 161.160 0.840 161.440 636.160 ;
      RECT 163.400 0.840 163.680 636.160 ;
      RECT 165.640 0.840 165.920 636.160 ;
      RECT 167.880 0.840 168.160 636.160 ;
      RECT 170.120 0.840 170.400 636.160 ;
      RECT 172.360 0.840 172.640 636.160 ;
      RECT 174.600 0.840 174.880 636.160 ;
      RECT 176.840 0.840 177.120 636.160 ;
      RECT 179.080 0.840 179.360 636.160 ;
      RECT 181.320 0.840 181.600 636.160 ;
      RECT 183.560 0.840 183.840 636.160 ;
      RECT 185.800 0.840 186.080 636.160 ;
      RECT 188.040 0.840 188.320 636.160 ;
      RECT 190.280 0.840 190.560 636.160 ;
      RECT 192.520 0.840 192.800 636.160 ;
      RECT 194.760 0.840 195.040 636.160 ;
      RECT 197.000 0.840 197.280 636.160 ;
      RECT 199.240 0.840 199.520 636.160 ;
      RECT 201.480 0.840 201.760 636.160 ;
      RECT 203.720 0.840 204.000 636.160 ;
      RECT 205.960 0.840 206.240 636.160 ;
      RECT 208.200 0.840 208.480 636.160 ;
      RECT 210.440 0.840 210.720 636.160 ;
      RECT 212.680 0.840 212.960 636.160 ;
      RECT 214.920 0.840 215.200 636.160 ;
      RECT 217.160 0.840 217.440 636.160 ;
      RECT 219.400 0.840 219.680 636.160 ;
      RECT 221.640 0.840 221.920 636.160 ;
      RECT 223.880 0.840 224.160 636.160 ;
      RECT 226.120 0.840 226.400 636.160 ;
      RECT 228.360 0.840 228.640 636.160 ;
      RECT 230.600 0.840 230.880 636.160 ;
      RECT 232.840 0.840 233.120 636.160 ;
      RECT 235.080 0.840 235.360 636.160 ;
      RECT 237.320 0.840 237.600 636.160 ;
      RECT 239.560 0.840 239.840 636.160 ;
      RECT 241.800 0.840 242.080 636.160 ;
      RECT 244.040 0.840 244.320 636.160 ;
      RECT 246.280 0.840 246.560 636.160 ;
      RECT 248.520 0.840 248.800 636.160 ;
      RECT 250.760 0.840 251.040 636.160 ;
      RECT 253.000 0.840 253.280 636.160 ;
      RECT 255.240 0.840 255.520 636.160 ;
      RECT 257.480 0.840 257.760 636.160 ;
      RECT 259.720 0.840 260.000 636.160 ;
      RECT 261.960 0.840 262.240 636.160 ;
      RECT 264.200 0.840 264.480 636.160 ;
      RECT 266.440 0.840 266.720 636.160 ;
      RECT 268.680 0.840 268.960 636.160 ;
      RECT 270.920 0.840 271.200 636.160 ;
      RECT 273.160 0.840 273.440 636.160 ;
      RECT 275.400 0.840 275.680 636.160 ;
      RECT 277.640 0.840 277.920 636.160 ;
      RECT 279.880 0.840 280.160 636.160 ;
      RECT 282.120 0.840 282.400 636.160 ;
      RECT 284.360 0.840 284.640 636.160 ;
      RECT 286.600 0.840 286.880 636.160 ;
      RECT 288.840 0.840 289.120 636.160 ;
      RECT 291.080 0.840 291.360 636.160 ;
      RECT 293.320 0.840 293.600 636.160 ;
      RECT 295.560 0.840 295.840 636.160 ;
      RECT 297.800 0.840 298.080 636.160 ;
      RECT 300.040 0.840 300.320 636.160 ;
      RECT 302.280 0.840 302.560 636.160 ;
      RECT 304.520 0.840 304.800 636.160 ;
      RECT 306.760 0.840 307.040 636.160 ;
      RECT 309.000 0.840 309.280 636.160 ;
      RECT 311.240 0.840 311.520 636.160 ;
      RECT 313.480 0.840 313.760 636.160 ;
      RECT 315.720 0.840 316.000 636.160 ;
      RECT 317.960 0.840 318.240 636.160 ;
      RECT 320.200 0.840 320.480 636.160 ;
      RECT 322.440 0.840 322.720 636.160 ;
      RECT 324.680 0.840 324.960 636.160 ;
      RECT 326.920 0.840 327.200 636.160 ;
      RECT 329.160 0.840 329.440 636.160 ;
      RECT 331.400 0.840 331.680 636.160 ;
      RECT 333.640 0.840 333.920 636.160 ;
      RECT 335.880 0.840 336.160 636.160 ;
      RECT 338.120 0.840 338.400 636.160 ;
      RECT 340.360 0.840 340.640 636.160 ;
      RECT 342.600 0.840 342.880 636.160 ;
      RECT 344.840 0.840 345.120 636.160 ;
      RECT 347.080 0.840 347.360 636.160 ;
      RECT 349.320 0.840 349.600 636.160 ;
      RECT 351.560 0.840 351.840 636.160 ;
      RECT 353.800 0.840 354.080 636.160 ;
      RECT 356.040 0.840 356.320 636.160 ;
      RECT 358.280 0.840 358.560 636.160 ;
      RECT 360.520 0.840 360.800 636.160 ;
      RECT 362.760 0.840 363.040 636.160 ;
      RECT 365.000 0.840 365.280 636.160 ;
      RECT 367.240 0.840 367.520 636.160 ;
      RECT 369.480 0.840 369.760 636.160 ;
      RECT 371.720 0.840 372.000 636.160 ;
      RECT 373.960 0.840 374.240 636.160 ;
      RECT 376.200 0.840 376.480 636.160 ;
      RECT 378.440 0.840 378.720 636.160 ;
      RECT 380.680 0.840 380.960 636.160 ;
      RECT 382.920 0.840 383.200 636.160 ;
      RECT 385.160 0.840 385.440 636.160 ;
      RECT 387.400 0.840 387.680 636.160 ;
      RECT 389.640 0.840 389.920 636.160 ;
      RECT 391.880 0.840 392.160 636.160 ;
      RECT 394.120 0.840 394.400 636.160 ;
      RECT 396.360 0.840 396.640 636.160 ;
      RECT 398.600 0.840 398.880 636.160 ;
      RECT 400.840 0.840 401.120 636.160 ;
      RECT 403.080 0.840 403.360 636.160 ;
      RECT 405.320 0.840 405.600 636.160 ;
      RECT 407.560 0.840 407.840 636.160 ;
      RECT 409.800 0.840 410.080 636.160 ;
      RECT 412.040 0.840 412.320 636.160 ;
      RECT 414.280 0.840 414.560 636.160 ;
      RECT 416.520 0.840 416.800 636.160 ;
      RECT 418.760 0.840 419.040 636.160 ;
      RECT 421.000 0.840 421.280 636.160 ;
      RECT 423.240 0.840 423.520 636.160 ;
      RECT 425.480 0.840 425.760 636.160 ;
      RECT 427.720 0.840 428.000 636.160 ;
      RECT 429.960 0.840 430.240 636.160 ;
      RECT 432.200 0.840 432.480 636.160 ;
      RECT 434.440 0.840 434.720 636.160 ;
      RECT 436.680 0.840 436.960 636.160 ;
      RECT 438.920 0.840 439.200 636.160 ;
      RECT 441.160 0.840 441.440 636.160 ;
      RECT 443.400 0.840 443.680 636.160 ;
      RECT 445.640 0.840 445.920 636.160 ;
      RECT 447.880 0.840 448.160 636.160 ;
      RECT 450.120 0.840 450.400 636.160 ;
      RECT 452.360 0.840 452.640 636.160 ;
      RECT 454.600 0.840 454.880 636.160 ;
      RECT 456.840 0.840 457.120 636.160 ;
      RECT 459.080 0.840 459.360 636.160 ;
      RECT 461.320 0.840 461.600 636.160 ;
      RECT 463.560 0.840 463.840 636.160 ;
      RECT 465.800 0.840 466.080 636.160 ;
      RECT 468.040 0.840 468.320 636.160 ;
      RECT 470.280 0.840 470.560 636.160 ;
      RECT 472.520 0.840 472.800 636.160 ;
      RECT 474.760 0.840 475.040 636.160 ;
      RECT 477.000 0.840 477.280 636.160 ;
      RECT 479.240 0.840 479.520 636.160 ;
      RECT 481.480 0.840 481.760 636.160 ;
      RECT 483.720 0.840 484.000 636.160 ;
      RECT 485.960 0.840 486.240 636.160 ;
      RECT 488.200 0.840 488.480 636.160 ;
      RECT 490.440 0.840 490.720 636.160 ;
      RECT 492.680 0.840 492.960 636.160 ;
      RECT 494.920 0.840 495.200 636.160 ;
      RECT 497.160 0.840 497.440 636.160 ;
      RECT 499.400 0.840 499.680 636.160 ;
      RECT 501.640 0.840 501.920 636.160 ;
      RECT 503.880 0.840 504.160 636.160 ;
      RECT 506.120 0.840 506.400 636.160 ;
      RECT 508.360 0.840 508.640 636.160 ;
      RECT 510.600 0.840 510.880 636.160 ;
      RECT 512.840 0.840 513.120 636.160 ;
      RECT 515.080 0.840 515.360 636.160 ;
      RECT 517.320 0.840 517.600 636.160 ;
      RECT 519.560 0.840 519.840 636.160 ;
      RECT 521.800 0.840 522.080 636.160 ;
      RECT 524.040 0.840 524.320 636.160 ;
      RECT 526.280 0.840 526.560 636.160 ;
      RECT 528.520 0.840 528.800 636.160 ;
      RECT 530.760 0.840 531.040 636.160 ;
      RECT 533.000 0.840 533.280 636.160 ;
      RECT 535.240 0.840 535.520 636.160 ;
      RECT 537.480 0.840 537.760 636.160 ;
      RECT 539.720 0.840 540.000 636.160 ;
      RECT 541.960 0.840 542.240 636.160 ;
      RECT 544.200 0.840 544.480 636.160 ;
      RECT 546.440 0.840 546.720 636.160 ;
      RECT 548.680 0.840 548.960 636.160 ;
      RECT 550.920 0.840 551.200 636.160 ;
      RECT 553.160 0.840 553.440 636.160 ;
      RECT 555.400 0.840 555.680 636.160 ;
      RECT 557.640 0.840 557.920 636.160 ;
      RECT 559.880 0.840 560.160 636.160 ;
      RECT 562.120 0.840 562.400 636.160 ;
      RECT 564.360 0.840 564.640 636.160 ;
      RECT 566.600 0.840 566.880 636.160 ;
      RECT 568.840 0.840 569.120 636.160 ;
      RECT 571.080 0.840 571.360 636.160 ;
      RECT 573.320 0.840 573.600 636.160 ;
      RECT 575.560 0.840 575.840 636.160 ;
      RECT 577.800 0.840 578.080 636.160 ;
      RECT 580.040 0.840 580.320 636.160 ;
      RECT 582.280 0.840 582.560 636.160 ;
      RECT 584.520 0.840 584.800 636.160 ;
      RECT 586.760 0.840 587.040 636.160 ;
      RECT 589.000 0.840 589.280 636.160 ;
      RECT 591.240 0.840 591.520 636.160 ;
      RECT 593.480 0.840 593.760 636.160 ;
      RECT 595.720 0.840 596.000 636.160 ;
      RECT 597.960 0.840 598.240 636.160 ;
      RECT 600.200 0.840 600.480 636.160 ;
      RECT 602.440 0.840 602.720 636.160 ;
      RECT 604.680 0.840 604.960 636.160 ;
      RECT 606.920 0.840 607.200 636.160 ;
      RECT 609.160 0.840 609.440 636.160 ;
      RECT 611.400 0.840 611.680 636.160 ;
      RECT 613.640 0.840 613.920 636.160 ;
      RECT 615.880 0.840 616.160 636.160 ;
      RECT 618.120 0.840 618.400 636.160 ;
      RECT 620.360 0.840 620.640 636.160 ;
      RECT 622.600 0.840 622.880 636.160 ;
      RECT 624.840 0.840 625.120 636.160 ;
      RECT 627.080 0.840 627.360 636.160 ;
      RECT 629.320 0.840 629.600 636.160 ;
      RECT 631.560 0.840 631.840 636.160 ;
      RECT 633.800 0.840 634.080 636.160 ;
      RECT 636.040 0.840 636.320 636.160 ;
      RECT 638.280 0.840 638.560 636.160 ;
      RECT 640.520 0.840 640.800 636.160 ;
      RECT 642.760 0.840 643.040 636.160 ;
      RECT 645.000 0.840 645.280 636.160 ;
      RECT 647.240 0.840 647.520 636.160 ;
      RECT 649.480 0.840 649.760 636.160 ;
      RECT 651.720 0.840 652.000 636.160 ;
      RECT 653.960 0.840 654.240 636.160 ;
      RECT 656.200 0.840 656.480 636.160 ;
      RECT 658.440 0.840 658.720 636.160 ;
      RECT 660.680 0.840 660.960 636.160 ;
      RECT 662.920 0.840 663.200 636.160 ;
      RECT 665.160 0.840 665.440 636.160 ;
      RECT 667.400 0.840 667.680 636.160 ;
      RECT 669.640 0.840 669.920 636.160 ;
      RECT 671.880 0.840 672.160 636.160 ;
      RECT 674.120 0.840 674.400 636.160 ;
      RECT 676.360 0.840 676.640 636.160 ;
      RECT 678.600 0.840 678.880 636.160 ;
      RECT 680.840 0.840 681.120 636.160 ;
      RECT 683.080 0.840 683.360 636.160 ;
      RECT 685.320 0.840 685.600 636.160 ;
      RECT 687.560 0.840 687.840 636.160 ;
      RECT 689.800 0.840 690.080 636.160 ;
      RECT 692.040 0.840 692.320 636.160 ;
      RECT 694.280 0.840 694.560 636.160 ;
      RECT 696.520 0.840 696.800 636.160 ;
      RECT 698.760 0.840 699.040 636.160 ;
      RECT 701.000 0.840 701.280 636.160 ;
      RECT 703.240 0.840 703.520 636.160 ;
      RECT 705.480 0.840 705.760 636.160 ;
      RECT 707.720 0.840 708.000 636.160 ;
      RECT 709.960 0.840 710.240 636.160 ;
      RECT 712.200 0.840 712.480 636.160 ;
      RECT 714.440 0.840 714.720 636.160 ;
      RECT 716.680 0.840 716.960 636.160 ;
      RECT 718.920 0.840 719.200 636.160 ;
      RECT 721.160 0.840 721.440 636.160 ;
      RECT 723.400 0.840 723.680 636.160 ;
      RECT 725.640 0.840 725.920 636.160 ;
      RECT 727.880 0.840 728.160 636.160 ;
      RECT 730.120 0.840 730.400 636.160 ;
      RECT 732.360 0.840 732.640 636.160 ;
      RECT 734.600 0.840 734.880 636.160 ;
      RECT 736.840 0.840 737.120 636.160 ;
      RECT 739.080 0.840 739.360 636.160 ;
      RECT 741.320 0.840 741.600 636.160 ;
      RECT 743.560 0.840 743.840 636.160 ;
      RECT 745.800 0.840 746.080 636.160 ;
      RECT 748.040 0.840 748.320 636.160 ;
      RECT 750.280 0.840 750.560 636.160 ;
      RECT 752.520 0.840 752.800 636.160 ;
      RECT 754.760 0.840 755.040 636.160 ;
      RECT 757.000 0.840 757.280 636.160 ;
      RECT 759.240 0.840 759.520 636.160 ;
      RECT 761.480 0.840 761.760 636.160 ;
      RECT 763.720 0.840 764.000 636.160 ;
      RECT 765.960 0.840 766.240 636.160 ;
      RECT 768.200 0.840 768.480 636.160 ;
      RECT 770.440 0.840 770.720 636.160 ;
      RECT 772.680 0.840 772.960 636.160 ;
      RECT 774.920 0.840 775.200 636.160 ;
      RECT 777.160 0.840 777.440 636.160 ;
      RECT 779.400 0.840 779.680 636.160 ;
      RECT 781.640 0.840 781.920 636.160 ;
      RECT 783.880 0.840 784.160 636.160 ;
      RECT 786.120 0.840 786.400 636.160 ;
      RECT 788.360 0.840 788.640 636.160 ;
      RECT 790.600 0.840 790.880 636.160 ;
      RECT 792.840 0.840 793.120 636.160 ;
      RECT 795.080 0.840 795.360 636.160 ;
      RECT 797.320 0.840 797.600 636.160 ;
      RECT 799.560 0.840 799.840 636.160 ;
      RECT 801.800 0.840 802.080 636.160 ;
      RECT 804.040 0.840 804.320 636.160 ;
      RECT 806.280 0.840 806.560 636.160 ;
      RECT 808.520 0.840 808.800 636.160 ;
      RECT 810.760 0.840 811.040 636.160 ;
      RECT 813.000 0.840 813.280 636.160 ;
      RECT 815.240 0.840 815.520 636.160 ;
      RECT 817.480 0.840 817.760 636.160 ;
      RECT 819.720 0.840 820.000 636.160 ;
      RECT 821.960 0.840 822.240 636.160 ;
      RECT 824.200 0.840 824.480 636.160 ;
      RECT 826.440 0.840 826.720 636.160 ;
      RECT 828.680 0.840 828.960 636.160 ;
      RECT 830.920 0.840 831.200 636.160 ;
      RECT 833.160 0.840 833.440 636.160 ;
      RECT 835.400 0.840 835.680 636.160 ;
      RECT 837.640 0.840 837.920 636.160 ;
      RECT 839.880 0.840 840.160 636.160 ;
      RECT 842.120 0.840 842.400 636.160 ;
      RECT 844.360 0.840 844.640 636.160 ;
      RECT 846.600 0.840 846.880 636.160 ;
      RECT 848.840 0.840 849.120 636.160 ;
      RECT 851.080 0.840 851.360 636.160 ;
      RECT 853.320 0.840 853.600 636.160 ;
      RECT 855.560 0.840 855.840 636.160 ;
      RECT 857.800 0.840 858.080 636.160 ;
      RECT 860.040 0.840 860.320 636.160 ;
      RECT 862.280 0.840 862.560 636.160 ;
      RECT 864.520 0.840 864.800 636.160 ;
      RECT 866.760 0.840 867.040 636.160 ;
      RECT 869.000 0.840 869.280 636.160 ;
      RECT 871.240 0.840 871.520 636.160 ;
      RECT 873.480 0.840 873.760 636.160 ;
      RECT 875.720 0.840 876.000 636.160 ;
      RECT 877.960 0.840 878.240 636.160 ;
      RECT 880.200 0.840 880.480 636.160 ;
      RECT 882.440 0.840 882.720 636.160 ;
      RECT 884.680 0.840 884.960 636.160 ;
      RECT 886.920 0.840 887.200 636.160 ;
      RECT 889.160 0.840 889.440 636.160 ;
      RECT 891.400 0.840 891.680 636.160 ;
      RECT 893.640 0.840 893.920 636.160 ;
      RECT 895.880 0.840 896.160 636.160 ;
      RECT 898.120 0.840 898.400 636.160 ;
      RECT 900.360 0.840 900.640 636.160 ;
      RECT 902.600 0.840 902.880 636.160 ;
      RECT 904.840 0.840 905.120 636.160 ;
      RECT 907.080 0.840 907.360 636.160 ;
      RECT 909.320 0.840 909.600 636.160 ;
      RECT 911.560 0.840 911.840 636.160 ;
      RECT 913.800 0.840 914.080 636.160 ;
      RECT 916.040 0.840 916.320 636.160 ;
      RECT 918.280 0.840 918.560 636.160 ;
      RECT 920.520 0.840 920.800 636.160 ;
      RECT 922.760 0.840 923.040 636.160 ;
      RECT 925.000 0.840 925.280 636.160 ;
      RECT 927.240 0.840 927.520 636.160 ;
      RECT 929.480 0.840 929.760 636.160 ;
      RECT 931.720 0.840 932.000 636.160 ;
      RECT 933.960 0.840 934.240 636.160 ;
      RECT 936.200 0.840 936.480 636.160 ;
      RECT 938.440 0.840 938.720 636.160 ;
      RECT 940.680 0.840 940.960 636.160 ;
      RECT 942.920 0.840 943.200 636.160 ;
      RECT 945.160 0.840 945.440 636.160 ;
      RECT 947.400 0.840 947.680 636.160 ;
      RECT 949.640 0.840 949.920 636.160 ;
      RECT 951.880 0.840 952.160 636.160 ;
      RECT 954.120 0.840 954.400 636.160 ;
      RECT 956.360 0.840 956.640 636.160 ;
      RECT 958.600 0.840 958.880 636.160 ;
      RECT 960.840 0.840 961.120 636.160 ;
      RECT 963.080 0.840 963.360 636.160 ;
      RECT 965.320 0.840 965.600 636.160 ;
      RECT 967.560 0.840 967.840 636.160 ;
      RECT 969.800 0.840 970.080 636.160 ;
      RECT 972.040 0.840 972.320 636.160 ;
      RECT 974.280 0.840 974.560 636.160 ;
      RECT 976.520 0.840 976.800 636.160 ;
      RECT 978.760 0.840 979.040 636.160 ;
      RECT 981.000 0.840 981.280 636.160 ;
      RECT 983.240 0.840 983.520 636.160 ;
      RECT 985.480 0.840 985.760 636.160 ;
      RECT 987.720 0.840 988.000 636.160 ;
      RECT 989.960 0.840 990.240 636.160 ;
      RECT 992.200 0.840 992.480 636.160 ;
      RECT 994.440 0.840 994.720 636.160 ;
      RECT 996.680 0.840 996.960 636.160 ;
      RECT 998.920 0.840 999.200 636.160 ;
      RECT 1001.160 0.840 1001.440 636.160 ;
      RECT 1003.400 0.840 1003.680 636.160 ;
      RECT 1005.640 0.840 1005.920 636.160 ;
      RECT 1007.880 0.840 1008.160 636.160 ;
      RECT 1010.120 0.840 1010.400 636.160 ;
      RECT 1012.360 0.840 1012.640 636.160 ;
      RECT 1014.600 0.840 1014.880 636.160 ;
      RECT 1016.840 0.840 1017.120 636.160 ;
      RECT 1019.080 0.840 1019.360 636.160 ;
      RECT 1021.320 0.840 1021.600 636.160 ;
      RECT 1023.560 0.840 1023.840 636.160 ;
      RECT 1025.800 0.840 1026.080 636.160 ;
      RECT 1028.040 0.840 1028.320 636.160 ;
      RECT 1030.280 0.840 1030.560 636.160 ;
      RECT 1032.520 0.840 1032.800 636.160 ;
      RECT 1034.760 0.840 1035.040 636.160 ;
      RECT 1037.000 0.840 1037.280 636.160 ;
      RECT 1039.240 0.840 1039.520 636.160 ;
      RECT 1041.480 0.840 1041.760 636.160 ;
      RECT 1043.720 0.840 1044.000 636.160 ;
      RECT 1045.960 0.840 1046.240 636.160 ;
      RECT 1048.200 0.840 1048.480 636.160 ;
      RECT 1050.440 0.840 1050.720 636.160 ;
      RECT 1052.680 0.840 1052.960 636.160 ;
      RECT 1054.920 0.840 1055.200 636.160 ;
      RECT 1057.160 0.840 1057.440 636.160 ;
      RECT 1059.400 0.840 1059.680 636.160 ;
      RECT 1061.640 0.840 1061.920 636.160 ;
      RECT 1063.880 0.840 1064.160 636.160 ;
      RECT 1066.120 0.840 1066.400 636.160 ;
      RECT 1068.360 0.840 1068.640 636.160 ;
      RECT 1070.600 0.840 1070.880 636.160 ;
      RECT 1072.840 0.840 1073.120 636.160 ;
      RECT 1075.080 0.840 1075.360 636.160 ;
      RECT 1077.320 0.840 1077.600 636.160 ;
      RECT 1079.560 0.840 1079.840 636.160 ;
      RECT 1081.800 0.840 1082.080 636.160 ;
      RECT 1084.040 0.840 1084.320 636.160 ;
      RECT 1086.280 0.840 1086.560 636.160 ;
      RECT 1088.520 0.840 1088.800 636.160 ;
      RECT 1090.760 0.840 1091.040 636.160 ;
      RECT 1093.000 0.840 1093.280 636.160 ;
      RECT 1095.240 0.840 1095.520 636.160 ;
      RECT 1097.480 0.840 1097.760 636.160 ;
      RECT 1099.720 0.840 1100.000 636.160 ;
      RECT 1101.960 0.840 1102.240 636.160 ;
      RECT 1104.200 0.840 1104.480 636.160 ;
      RECT 1106.440 0.840 1106.720 636.160 ;
      RECT 1108.680 0.840 1108.960 636.160 ;
      RECT 1110.920 0.840 1111.200 636.160 ;
      RECT 1113.160 0.840 1113.440 636.160 ;
      RECT 1115.400 0.840 1115.680 636.160 ;
      RECT 1117.640 0.840 1117.920 636.160 ;
      RECT 1119.880 0.840 1120.160 636.160 ;
      RECT 1122.120 0.840 1122.400 636.160 ;
      RECT 1124.360 0.840 1124.640 636.160 ;
      RECT 1126.600 0.840 1126.880 636.160 ;
      RECT 1128.840 0.840 1129.120 636.160 ;
      RECT 1131.080 0.840 1131.360 636.160 ;
      RECT 1133.320 0.840 1133.600 636.160 ;
      RECT 1135.560 0.840 1135.840 636.160 ;
      RECT 1137.800 0.840 1138.080 636.160 ;
      RECT 1140.040 0.840 1140.320 636.160 ;
      RECT 1142.280 0.840 1142.560 636.160 ;
      RECT 1144.520 0.840 1144.800 636.160 ;
      RECT 1146.760 0.840 1147.040 636.160 ;
      RECT 1149.000 0.840 1149.280 636.160 ;
      RECT 1151.240 0.840 1151.520 636.160 ;
      RECT 1153.480 0.840 1153.760 636.160 ;
      RECT 1155.720 0.840 1156.000 636.160 ;
      RECT 1157.960 0.840 1158.240 636.160 ;
      RECT 1160.200 0.840 1160.480 636.160 ;
      RECT 1162.440 0.840 1162.720 636.160 ;
      RECT 1164.680 0.840 1164.960 636.160 ;
      RECT 1166.920 0.840 1167.200 636.160 ;
      RECT 1169.160 0.840 1169.440 636.160 ;
      RECT 1171.400 0.840 1171.680 636.160 ;
      RECT 1173.640 0.840 1173.920 636.160 ;
      RECT 1175.880 0.840 1176.160 636.160 ;
      RECT 1178.120 0.840 1178.400 636.160 ;
      RECT 1180.360 0.840 1180.640 636.160 ;
      RECT 1182.600 0.840 1182.880 636.160 ;
      RECT 1184.840 0.840 1185.120 636.160 ;
      RECT 1187.080 0.840 1187.360 636.160 ;
      RECT 1189.320 0.840 1189.600 636.160 ;
      RECT 1191.560 0.840 1191.840 636.160 ;
      RECT 1193.800 0.840 1194.080 636.160 ;
      RECT 1196.040 0.840 1196.320 636.160 ;
      RECT 1198.280 0.840 1198.560 636.160 ;
      RECT 1200.520 0.840 1200.800 636.160 ;
      RECT 1202.760 0.840 1203.040 636.160 ;
      RECT 1205.000 0.840 1205.280 636.160 ;
      RECT 1207.240 0.840 1207.520 636.160 ;
      RECT 1209.480 0.840 1209.760 636.160 ;
      RECT 1211.720 0.840 1212.000 636.160 ;
      RECT 1213.960 0.840 1214.240 636.160 ;
      RECT 1216.200 0.840 1216.480 636.160 ;
      RECT 1218.440 0.840 1218.720 636.160 ;
      RECT 1220.680 0.840 1220.960 636.160 ;
      RECT 1222.920 0.840 1223.200 636.160 ;
      RECT 1225.160 0.840 1225.440 636.160 ;
      RECT 1227.400 0.840 1227.680 636.160 ;
      RECT 1229.640 0.840 1229.920 636.160 ;
      RECT 1231.880 0.840 1232.160 636.160 ;
      RECT 1234.120 0.840 1234.400 636.160 ;
      RECT 1236.360 0.840 1236.640 636.160 ;
      RECT 1238.600 0.840 1238.880 636.160 ;
      RECT 1240.840 0.840 1241.120 636.160 ;
      RECT 1243.080 0.840 1243.360 636.160 ;
      RECT 1245.320 0.840 1245.600 636.160 ;
      RECT 1247.560 0.840 1247.840 636.160 ;
      RECT 1249.800 0.840 1250.080 636.160 ;
      RECT 1252.040 0.840 1252.320 636.160 ;
      RECT 1254.280 0.840 1254.560 636.160 ;
      RECT 1256.520 0.840 1256.800 636.160 ;
      RECT 1258.760 0.840 1259.040 636.160 ;
      RECT 1261.000 0.840 1261.280 636.160 ;
      RECT 1263.240 0.840 1263.520 636.160 ;
      RECT 1265.480 0.840 1265.760 636.160 ;
      RECT 1267.720 0.840 1268.000 636.160 ;
      RECT 1269.960 0.840 1270.240 636.160 ;
      RECT 1272.200 0.840 1272.480 636.160 ;
      RECT 1274.440 0.840 1274.720 636.160 ;
      RECT 1276.680 0.840 1276.960 636.160 ;
      RECT 1278.920 0.840 1279.200 636.160 ;
      RECT 1281.160 0.840 1281.440 636.160 ;
      RECT 1283.400 0.840 1283.680 636.160 ;
      RECT 1285.640 0.840 1285.920 636.160 ;
      RECT 1287.880 0.840 1288.160 636.160 ;
      RECT 1290.120 0.840 1290.400 636.160 ;
      RECT 1292.360 0.840 1292.640 636.160 ;
      RECT 1294.600 0.840 1294.880 636.160 ;
      RECT 1296.840 0.840 1297.120 636.160 ;
      RECT 1299.080 0.840 1299.360 636.160 ;
      RECT 1301.320 0.840 1301.600 636.160 ;
      RECT 1303.560 0.840 1303.840 636.160 ;
      RECT 1305.800 0.840 1306.080 636.160 ;
      RECT 1308.040 0.840 1308.320 636.160 ;
      RECT 1310.280 0.840 1310.560 636.160 ;
      RECT 1312.520 0.840 1312.800 636.160 ;
      RECT 1314.760 0.840 1315.040 636.160 ;
      RECT 1317.000 0.840 1317.280 636.160 ;
      RECT 1319.240 0.840 1319.520 636.160 ;
      RECT 1321.480 0.840 1321.760 636.160 ;
      RECT 1323.720 0.840 1324.000 636.160 ;
      RECT 1325.960 0.840 1326.240 636.160 ;
      RECT 1328.200 0.840 1328.480 636.160 ;
      RECT 1330.440 0.840 1330.720 636.160 ;
      RECT 1332.680 0.840 1332.960 636.160 ;
      RECT 1334.920 0.840 1335.200 636.160 ;
      RECT 1337.160 0.840 1337.440 636.160 ;
      RECT 1339.400 0.840 1339.680 636.160 ;
      RECT 1341.640 0.840 1341.920 636.160 ;
      RECT 1343.880 0.840 1344.160 636.160 ;
      RECT 1346.120 0.840 1346.400 636.160 ;
      RECT 1348.360 0.840 1348.640 636.160 ;
      RECT 1350.600 0.840 1350.880 636.160 ;
      RECT 1352.840 0.840 1353.120 636.160 ;
      RECT 1355.080 0.840 1355.360 636.160 ;
      RECT 1357.320 0.840 1357.600 636.160 ;
      RECT 1359.560 0.840 1359.840 636.160 ;
      RECT 1361.800 0.840 1362.080 636.160 ;
      RECT 1364.040 0.840 1364.320 636.160 ;
      RECT 1366.280 0.840 1366.560 636.160 ;
      RECT 1368.520 0.840 1368.800 636.160 ;
      RECT 1370.760 0.840 1371.040 636.160 ;
      RECT 1373.000 0.840 1373.280 636.160 ;
      RECT 1375.240 0.840 1375.520 636.160 ;
      RECT 1377.480 0.840 1377.760 636.160 ;
      RECT 1379.720 0.840 1380.000 636.160 ;
      RECT 1381.960 0.840 1382.240 636.160 ;
      RECT 1384.200 0.840 1384.480 636.160 ;
      RECT 1386.440 0.840 1386.720 636.160 ;
      RECT 1388.680 0.840 1388.960 636.160 ;
      RECT 1390.920 0.840 1391.200 636.160 ;
      RECT 1393.160 0.840 1393.440 636.160 ;
      RECT 1395.400 0.840 1395.680 636.160 ;
      RECT 1397.640 0.840 1397.920 636.160 ;
      RECT 1399.880 0.840 1400.160 636.160 ;
      RECT 1402.120 0.840 1402.400 636.160 ;
      RECT 1404.360 0.840 1404.640 636.160 ;
      RECT 1406.600 0.840 1406.880 636.160 ;
      RECT 1408.840 0.840 1409.120 636.160 ;
      RECT 1411.080 0.840 1411.360 636.160 ;
      RECT 1413.320 0.840 1413.600 636.160 ;
      RECT 1415.560 0.840 1415.840 636.160 ;
      RECT 1417.800 0.840 1418.080 636.160 ;
      RECT 1420.040 0.840 1420.320 636.160 ;
      RECT 1422.280 0.840 1422.560 636.160 ;
      RECT 1424.520 0.840 1424.800 636.160 ;
      RECT 1426.760 0.840 1427.040 636.160 ;
      RECT 1429.000 0.840 1429.280 636.160 ;
      RECT 1431.240 0.840 1431.520 636.160 ;
      RECT 1433.480 0.840 1433.760 636.160 ;
      RECT 1435.720 0.840 1436.000 636.160 ;
      RECT 1437.960 0.840 1438.240 636.160 ;
      RECT 1440.200 0.840 1440.480 636.160 ;
      RECT 1442.440 0.840 1442.720 636.160 ;
      RECT 1444.680 0.840 1444.960 636.160 ;
      RECT 1446.920 0.840 1447.200 636.160 ;
      RECT 1449.160 0.840 1449.440 636.160 ;
      RECT 1451.400 0.840 1451.680 636.160 ;
      RECT 1453.640 0.840 1453.920 636.160 ;
      RECT 1455.880 0.840 1456.160 636.160 ;
      RECT 1458.120 0.840 1458.400 636.160 ;
      RECT 1460.360 0.840 1460.640 636.160 ;
    END
  END VDD
  OBS
    LAYER metal1 ;
    RECT 0 0 1461.480 637.000 ;
    LAYER metal2 ;
    RECT 0 0 1461.480 637.000 ;
    LAYER metal3 ;
    RECT 0 0 1461.480 637.000 ;
    LAYER metal4 ;
    RECT 0 0 1461.480 637.000 ;
    LAYER OVERLAP ;
    RECT 0 0 1461.480 637.000 ;
  END
END fakeram_w64_l16384

END LIBRARY
